# CM05: LEF escalado desde osu050 (OSU, AMI C5) por factor 25/3 -> lambda = 2.5 um, 2 metales.
# RESISTANCE/CAPACITANCE heredados de AMI C5: APROXIMADOS, no medidos en CM05.
# LEF file generated by Abstract Generator version 5.5.10 on Jul 31 16:51:52 2004
#
# Contains LEF for all bins.
# Options:   [x] Antenna
#            [x] Geometry
#            [x] Technology

VERSION 5.4 ;
NAMESCASESENSITIVE ON ;
BUSBITCHARS "[]" ;
DIVIDERCHAR "/" ;
UNITS
  DATABASE MICRONS 1000 ;
END UNITS

USEMINSPACING OBS ON ;
USEMINSPACING PIN OFF ;
CLEARANCEMEASURE EUCLIDEAN ;


MANUFACTURINGGRID 1.250 ;

LAYER nwell
  TYPE	MASTERSLICE ;
END nwell

LAYER nactive
  TYPE	MASTERSLICE ;
END nactive

LAYER pactive
  TYPE	MASTERSLICE ;
END pactive

LAYER poly
  TYPE	MASTERSLICE ;
END poly

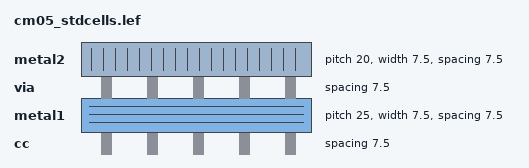
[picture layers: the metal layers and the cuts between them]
LAYER cc
  TYPE	CUT ;
  SPACING	7.500 ;
END cc

LAYER metal1
  TYPE		ROUTING ;
  DIRECTION	HORIZONTAL ;
  PITCH		25.000  ;
  OFFSET	12.500 ;
  WIDTH		7.500 ;
  SPACING	7.500 ;
  RESISTANCE	RPERSQ 0.09 ;
  CAPACITANCE	CPERSQDIST 3.2e-05 ;
END metal1

LAYER via
  TYPE	CUT ;
  SPACING	7.500 ;
END via

LAYER metal2
  TYPE		ROUTING ;
  DIRECTION	VERTICAL ;
  PITCH		20.000  ;
  OFFSET	10.000 ;
  WIDTH		7.500 ;
  SPACING	7.500 ;
  RESISTANCE	RPERSQ 0.09 ;
  CAPACITANCE	CPERSQDIST 1.6e-05 ;
END metal2




VIA M2_M1 DEFAULT
  LAYER metal1 ;
    RECT -5.000 -5.000 5.000 5.000 ;
  LAYER via ;
    RECT -2.500 -2.500 2.500 2.500 ;
  LAYER metal2 ;
    RECT -5.000 -5.000 5.000 5.000 ;
END M2_M1



VIARULE viagen21 GENERATE
  LAYER metal1 ;
    DIRECTION HORIZONTAL ;
    WIDTH 10.000 TO 1000.000 ;
    OVERHANG 2.500 ;
    METALOVERHANG 0.000 ;
  LAYER metal2 ;
    DIRECTION VERTICAL ;
    WIDTH 10.000 TO 1000.000 ;
    OVERHANG 2.500 ;
    METALOVERHANG 0.000 ;
  LAYER via ;
    RECT -2.500 -2.500 2.500 2.500 ;
    SPACING 12.500 BY 12.500 ;
END viagen21


VIARULE TURN1 GENERATE
  LAYER metal1 ;
    DIRECTION HORIZONTAL ;
  LAYER metal1 ;
    DIRECTION VERTICAL ;
END TURN1

VIARULE TURN2 GENERATE
  LAYER metal2 ;
    DIRECTION HORIZONTAL ;
  LAYER metal2 ;
    DIRECTION VERTICAL ;
END TURN2




SITE  core
    CLASS	CORE ;
    SYMMETRY	Y ;
    SIZE	20.000 BY 250.000 ;
END  core

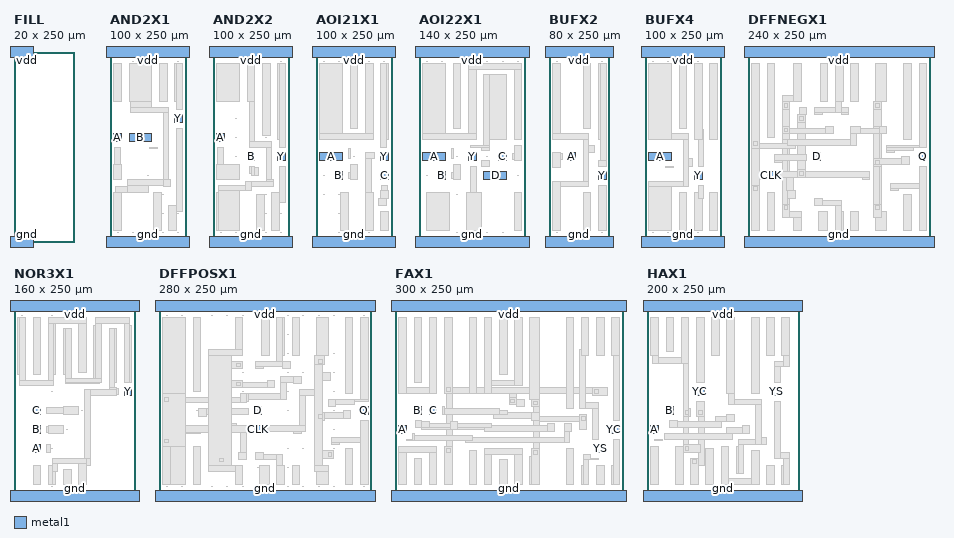
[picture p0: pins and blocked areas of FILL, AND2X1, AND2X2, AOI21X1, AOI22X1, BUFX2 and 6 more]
MACRO FILL
  CLASS  CORE ;
  FOREIGN FILL 0.000 0.000 ;
  ORIGIN 0.000 0.000 ;
  SIZE 20.000 BY 250.000 ;
  SYMMETRY X Y  ;
  SITE core ;
  PIN gnd
    DIRECTION INOUT ;
    USE GROUND ;
    SHAPE ABUTMENT ;
    PORT
      LAYER metal1 ;
        RECT -5.000 -7.500 25.000 7.500 ;
    END
  END gnd
  PIN vdd
    DIRECTION INOUT ;
    USE POWER ;
    SHAPE ABUTMENT ;
    PORT
      LAYER metal1 ;
        RECT -5.000 242.500 25.000 257.500 ;
    END
  END vdd
END FILL

MACRO AND2X1
  CLASS  CORE ;
  FOREIGN AND2X1 0.000 0.000 ;
  ORIGIN 0.000 0.000 ;
  SIZE 100.000 BY 250.000 ;
  SYMMETRY X Y  ;
  SITE core ;
  PIN A
    DIRECTION INPUT ;
    PORT
      LAYER metal1 ;
        RECT 5.000 132.500 15.000 142.500 ;
    END
  END A
  PIN B
    DIRECTION INPUT ;
    PORT
      LAYER metal1 ;
        RECT 25.000 132.500 55.000 142.500 ;
    END
  END B
  PIN gnd
    DIRECTION INOUT ;
    USE GROUND ;
    SHAPE ABUTMENT ;
    PORT
      LAYER metal1 ;
        RECT -5.000 -7.500 105.000 7.500 ;
    END
  END gnd
  PIN Y
    DIRECTION OUTPUT ;
    PORT
      LAYER metal1 ;
        RECT 85.000 157.500 95.000 167.500 ;
    END
  END Y
  PIN vdd
    DIRECTION INOUT ;
    USE POWER ;
    SHAPE ABUTMENT ;
    PORT
      LAYER metal1 ;
        RECT -5.000 242.500 105.000 257.500 ;
    END
  END vdd
  OBS
      LAYER metal1 ;
        RECT 9.375 11.875 10.625 13.125 ;
        RECT 29.375 11.875 30.625 13.125 ;
        RECT 29.375 236.875 30.625 238.125 ;
        RECT 49.375 11.875 50.625 13.125 ;
        RECT 49.375 86.875 50.625 88.125 ;
        RECT 49.375 236.875 50.625 238.125 ;
        RECT 69.375 11.875 70.625 13.125 ;
        RECT 69.375 36.875 70.625 38.125 ;
        RECT 69.375 61.875 70.625 63.125 ;
        RECT 89.375 11.875 90.625 13.125 ;
        RECT 89.375 36.875 90.625 38.125 ;
        RECT 89.375 236.875 90.625 238.125 ;
      LAYER metal1 ;
        RECT 57.500 15.000 67.500 65.000 ;
        RECT 6.250 102.500 13.750 125.000 ;
        RECT 5.000 82.500 15.000 102.500 ;
        RECT 52.500 122.500 62.500 125.000 ;
        RECT 87.500 40.000 95.000 150.000 ;
        RECT 77.500 15.000 87.500 47.500 ;
        RECT 5.000 185.000 15.000 235.000 ;
        RECT 22.500 65.000 50.000 75.000 ;
        RECT 5.000 15.000 15.000 65.000 ;
        RECT 7.500 65.000 22.500 72.500 ;
        RECT 22.500 75.000 70.000 82.500 ;
        RECT 27.500 170.000 77.500 177.500 ;
        RECT 70.000 72.500 80.000 82.500 ;
        RECT 70.000 82.500 77.500 170.000 ;
        RECT 25.000 185.000 55.000 235.000 ;
        RECT 27.500 177.500 55.000 185.000 ;
        RECT 65.000 185.000 75.000 235.000 ;
        RECT 85.000 185.000 87.500 235.000 ;
        RECT 87.500 175.000 95.000 235.000 ;
  END 
END AND2X1

MACRO AND2X2
  CLASS  CORE ;
  FOREIGN AND2X2 0.000 0.000 ;
  ORIGIN 0.000 0.000 ;
  SIZE 100.000 BY 250.000 ;
  SYMMETRY X Y  ;
  SITE core ;
  PIN A
    DIRECTION INPUT ;
    PORT
      LAYER metal1 ;
        RECT 5.000 132.500 15.000 142.500 ;
    END
  END A
  PIN B
    DIRECTION INPUT ;
    PORT
      LAYER metal1 ;
        RECT 45.000 107.500 55.000 117.500 ;
    END
  END B
  PIN gnd
    DIRECTION INOUT ;
    USE GROUND ;
    SHAPE ABUTMENT ;
    PORT
      LAYER metal1 ;
        RECT -5.000 -7.500 105.000 7.500 ;
    END
  END gnd
  PIN Y
    DIRECTION OUTPUT ;
    PORT
      LAYER metal1 ;
        RECT 85.000 107.500 95.000 117.500 ;
    END
  END Y
  PIN vdd
    DIRECTION INOUT ;
    USE POWER ;
    SHAPE ABUTMENT ;
    PORT
      LAYER metal1 ;
        RECT -5.000 242.500 105.000 257.500 ;
    END
  END vdd
  OBS
      LAYER metal1 ;
        RECT 9.375 11.875 10.625 13.125 ;
        RECT 29.375 11.875 30.625 13.125 ;
        RECT 29.375 111.875 30.625 113.125 ;
        RECT 29.375 136.875 30.625 138.125 ;
        RECT 29.375 161.875 30.625 163.125 ;
        RECT 49.375 11.875 50.625 13.125 ;
        RECT 49.375 236.875 50.625 238.125 ;
        RECT 69.375 11.875 70.625 13.125 ;
        RECT 69.375 36.875 70.625 38.125 ;
        RECT 69.375 61.875 70.625 63.125 ;
        RECT 69.375 136.875 70.625 138.125 ;
        RECT 89.375 11.875 90.625 13.125 ;
        RECT 89.375 36.875 90.625 38.125 ;
        RECT 89.375 236.875 90.625 238.125 ;
      LAYER metal1 ;
        RECT 57.500 15.000 67.500 62.500 ;
        RECT 55.000 87.500 60.000 97.500 ;
        RECT 47.500 90.000 50.000 100.000 ;
        RECT 50.000 87.500 55.000 100.000 ;
        RECT 87.500 52.500 95.000 100.000 ;
        RECT 77.500 15.000 87.500 65.000 ;
        RECT 6.250 102.500 13.750 125.000 ;
        RECT 5.000 82.500 35.000 102.500 ;
        RECT 5.000 185.000 35.000 235.000 ;
        RECT 47.500 125.000 77.500 132.500 ;
        RECT 70.000 80.000 80.000 82.500 ;
        RECT 70.000 82.500 77.500 125.000 ;
        RECT 42.500 67.500 50.000 80.000 ;
        RECT 50.000 72.500 80.000 80.000 ;
        RECT 45.000 185.000 55.000 235.000 ;
        RECT 47.500 132.500 55.000 185.000 ;
        RECT 7.500 15.000 35.000 67.500 ;
        RECT 5.000 15.000 7.500 65.000 ;
        RECT 7.500 67.500 42.500 75.000 ;
        RECT 65.000 140.000 75.000 235.000 ;
        RECT 85.000 135.000 87.500 235.000 ;
        RECT 87.500 125.000 95.000 235.000 ;
  END 
END AND2X2

MACRO AOI21X1
  CLASS  CORE ;
  FOREIGN AOI21X1 0.000 0.000 ;
  ORIGIN 0.000 0.000 ;
  SIZE 100.000 BY 250.000 ;
  SYMMETRY X Y  ;
  SITE core ;
  PIN A
    DIRECTION INPUT ;
    PORT
      LAYER metal1 ;
        RECT 5.000 107.500 35.000 117.500 ;
    END
  END A
  PIN B
    DIRECTION INPUT ;
    PORT
      LAYER metal1 ;
        RECT 25.000 82.500 35.000 92.500 ;
    END
  END B
  PIN C
    DIRECTION INPUT ;
    PORT
      LAYER metal1 ;
        RECT 85.000 82.500 95.000 92.500 ;
    END
  END C
  PIN gnd
    DIRECTION INOUT ;
    USE GROUND ;
    SHAPE ABUTMENT ;
    PORT
      LAYER metal1 ;
        RECT -5.000 -7.500 105.000 7.500 ;
    END
  END gnd
  PIN Y
    DIRECTION OUTPUT ;
    PORT
      LAYER metal1 ;
        RECT 85.000 107.500 95.000 117.500 ;
    END
  END Y
  PIN vdd
    DIRECTION INOUT ;
    USE POWER ;
    SHAPE ABUTMENT ;
    PORT
      LAYER metal1 ;
        RECT -5.000 242.500 105.000 257.500 ;
    END
  END vdd
  OBS
      LAYER metal1 ;
        RECT 9.375 61.875 10.625 63.125 ;
        RECT 9.375 86.875 10.625 88.125 ;
        RECT 9.375 236.875 10.625 238.125 ;
        RECT 29.375 11.875 30.625 13.125 ;
        RECT 29.375 36.875 30.625 38.125 ;
        RECT 29.375 61.875 30.625 63.125 ;
        RECT 29.375 236.875 30.625 238.125 ;
        RECT 49.375 11.875 50.625 13.125 ;
        RECT 49.375 111.875 50.625 113.125 ;
        RECT 69.375 11.875 70.625 13.125 ;
        RECT 69.375 236.875 70.625 238.125 ;
        RECT 89.375 236.875 90.625 238.125 ;
      LAYER metal1 ;
        RECT 85.000 15.000 95.000 40.000 ;
        RECT 32.500 15.000 42.500 65.000 ;
        RECT 86.250 67.500 93.750 75.000 ;
        RECT 85.000 57.500 95.000 67.500 ;
        RECT 82.500 47.500 92.500 57.500 ;
        RECT 45.000 82.500 55.000 102.500 ;
        RECT 42.500 83.750 45.000 91.250 ;
        RECT 65.000 15.000 75.000 65.000 ;
        RECT 65.000 65.000 72.500 110.000 ;
        RECT 65.000 110.000 77.500 117.500 ;
        RECT 42.500 110.000 45.000 122.500 ;
        RECT 45.000 150.000 55.000 235.000 ;
        RECT 5.000 142.500 35.000 235.000 ;
        RECT 65.000 142.500 75.000 235.000 ;
        RECT 5.000 135.000 75.000 142.500 ;
        RECT 85.000 125.000 92.500 235.000 ;
        RECT 92.500 135.000 95.000 235.000 ;
  END 
END AOI21X1

MACRO AOI22X1
  CLASS  CORE ;
  FOREIGN AOI22X1 0.000 0.000 ;
  ORIGIN 0.000 0.000 ;
  SIZE 140.000 BY 250.000 ;
  SYMMETRY X Y  ;
  SITE core ;
  PIN A
    DIRECTION INPUT ;
    PORT
      LAYER metal1 ;
        RECT 5.000 107.500 35.000 117.500 ;
    END
  END A
  PIN B
    DIRECTION INPUT ;
    PORT
      LAYER metal1 ;
        RECT 25.000 82.500 35.000 92.500 ;
    END
  END B
  PIN C
    DIRECTION INPUT ;
    PORT
      LAYER metal1 ;
        RECT 105.000 107.500 115.000 117.500 ;
    END
  END C
  PIN D
    DIRECTION INPUT ;
    PORT
      LAYER metal1 ;
        RECT 85.000 82.500 115.000 92.500 ;
    END
  END D
  PIN gnd
    DIRECTION INOUT ;
    USE GROUND ;
    SHAPE ABUTMENT ;
    PORT
      LAYER metal1 ;
        RECT -5.000 -7.500 145.000 7.500 ;
    END
  END gnd
  PIN Y
    DIRECTION OUTPUT ;
    PORT
      LAYER metal1 ;
        RECT 65.000 107.500 75.000 117.500 ;
    END
  END Y
  PIN vdd
    DIRECTION INOUT ;
    USE POWER ;
    SHAPE ABUTMENT ;
    PORT
      LAYER metal1 ;
        RECT -5.000 242.500 145.000 257.500 ;
    END
  END vdd
  OBS
      LAYER metal1 ;
        RECT 9.375 86.875 10.625 88.125 ;
        RECT 9.375 236.875 10.625 238.125 ;
        RECT 29.375 236.875 30.625 238.125 ;
        RECT 49.375 11.875 50.625 13.125 ;
        RECT 49.375 61.875 50.625 63.125 ;
        RECT 49.375 111.875 50.625 113.125 ;
        RECT 69.375 11.875 70.625 13.125 ;
        RECT 69.375 236.875 70.625 238.125 ;
        RECT 89.375 11.875 90.625 13.125 ;
        RECT 89.375 111.875 90.625 113.125 ;
        RECT 89.375 236.875 90.625 238.125 ;
        RECT 109.375 11.875 110.625 13.125 ;
        RECT 109.375 236.875 110.625 238.125 ;
        RECT 129.375 86.875 130.625 88.125 ;
        RECT 129.375 236.875 130.625 238.125 ;
      LAYER metal1 ;
        RECT 10.000 15.000 40.000 65.000 ;
        RECT 125.000 15.000 135.000 65.000 ;
        RECT 62.500 15.000 82.500 65.000 ;
        RECT 67.500 65.000 75.000 100.000 ;
        RECT 45.000 82.500 55.000 102.500 ;
        RECT 42.500 83.750 45.000 91.250 ;
        RECT 82.500 100.000 92.500 107.500 ;
        RECT 42.500 110.000 45.000 122.500 ;
        RECT 125.000 107.500 135.000 127.500 ;
        RECT 122.500 108.750 125.000 116.250 ;
        RECT 85.000 127.500 92.500 220.000 ;
        RECT 67.500 125.000 92.500 127.500 ;
        RECT 82.500 120.000 92.500 125.000 ;
        RECT 92.500 135.000 115.000 220.000 ;
        RECT 45.000 150.000 55.000 235.000 ;
        RECT 65.000 142.500 75.000 227.500 ;
        RECT 5.000 135.000 75.000 142.500 ;
        RECT 5.000 142.500 35.000 235.000 ;
        RECT 65.000 227.500 135.000 235.000 ;
        RECT 125.000 135.000 135.000 227.500 ;
  END 
END AOI22X1

MACRO BUFX2
  CLASS  CORE ;
  FOREIGN BUFX2 0.000 0.000 ;
  ORIGIN 0.000 0.000 ;
  SIZE 80.000 BY 250.000 ;
  SYMMETRY X Y  ;
  SITE core ;
  PIN A
    DIRECTION INPUT ;
    PORT
      LAYER metal1 ;
        RECT 25.000 107.500 35.000 117.500 ;
    END
  END A
  PIN gnd
    DIRECTION INOUT ;
    USE GROUND ;
    SHAPE ABUTMENT ;
    PORT
      LAYER metal1 ;
        RECT -5.000 -7.500 85.000 7.500 ;
    END
  END gnd
  PIN Y
    DIRECTION OUTPUT ;
    PORT
      LAYER metal1 ;
        RECT 65.000 82.500 75.000 92.500 ;
    END
  END Y
  PIN vdd
    DIRECTION INOUT ;
    USE POWER ;
    SHAPE ABUTMENT ;
    PORT
      LAYER metal1 ;
        RECT -5.000 242.500 85.000 257.500 ;
    END
  END vdd
  OBS
      LAYER metal1 ;
        RECT 9.375 11.875 10.625 13.125 ;
        RECT 9.375 236.875 10.625 238.125 ;
        RECT 29.375 11.875 30.625 13.125 ;
        RECT 29.375 236.875 30.625 238.125 ;
        RECT 69.375 11.875 70.625 13.125 ;
        RECT 69.375 236.875 70.625 238.125 ;
      LAYER metal1 ;
        RECT 45.000 15.000 55.000 65.000 ;
        RECT 65.000 15.000 75.000 75.000 ;
        RECT 5.000 97.500 15.000 117.500 ;
        RECT 15.000 108.750 17.500 116.250 ;
        RECT 52.500 117.500 60.000 127.500 ;
        RECT 5.000 135.000 52.500 142.500 ;
        RECT 5.000 142.500 15.000 235.000 ;
        RECT 5.000 15.000 15.000 80.000 ;
        RECT 45.000 80.000 52.500 135.000 ;
        RECT 15.000 72.500 52.500 80.000 ;
        RECT 45.000 150.000 55.000 235.000 ;
        RECT 65.000 135.000 67.500 235.000 ;
        RECT 67.500 107.500 75.000 235.000 ;
        RECT 65.000 100.000 75.000 107.500 ;
  END 
END BUFX2

MACRO BUFX4
  CLASS  CORE ;
  FOREIGN BUFX4 0.000 0.000 ;
  ORIGIN 0.000 0.000 ;
  SIZE 100.000 BY 250.000 ;
  SYMMETRY X Y  ;
  SITE core ;
  PIN A
    DIRECTION INPUT ;
    PORT
      LAYER metal1 ;
        RECT 5.000 107.500 35.000 117.500 ;
    END
  END A
  PIN gnd
    DIRECTION INOUT ;
    USE GROUND ;
    SHAPE ABUTMENT ;
    PORT
      LAYER metal1 ;
        RECT -5.000 -7.500 105.000 7.500 ;
    END
  END gnd
  PIN Y
    DIRECTION OUTPUT ;
    PORT
      LAYER metal1 ;
        RECT 65.000 82.500 75.000 92.500 ;
    END
  END Y
  PIN vdd
    DIRECTION INOUT ;
    USE POWER ;
    SHAPE ABUTMENT ;
    PORT
      LAYER metal1 ;
        RECT -5.000 242.500 105.000 257.500 ;
    END
  END vdd
  OBS 
      LAYER metal1 ;
        RECT 9.375 11.875 10.625 13.125 ;
        RECT 9.375 236.875 10.625 238.125 ;
        RECT 29.375 11.875 30.625 13.125 ;
        RECT 29.375 236.875 30.625 238.125 ;
        RECT 69.375 11.875 70.625 13.125 ;
        RECT 69.375 236.875 70.625 238.125 ;
      LAYER metal1 ;
        RECT 27.500 97.500 37.500 100.000 ;
        RECT 45.000 150.000 55.000 235.000 ;
        RECT 45.000 15.000 55.000 65.000 ;
        RECT 5.000 15.000 35.000 80.000 ;
        RECT 5.000 72.500 57.500 80.000 ;
        RECT 50.000 100.000 62.500 110.000 ;
        RECT 50.000 72.500 57.500 142.500 ;
        RECT 5.000 135.000 57.500 142.500 ;
        RECT 5.000 135.000 35.000 235.000 ;
        RECT 70.000 100.000 77.500 147.500 ;
        RECT 65.000 135.000 75.000 235.000 ;
        RECT 65.000 15.000 75.000 65.000 ;
        RECT 70.000 57.500 77.500 75.000 ;
        RECT 85.000 135.000 95.000 235.000 ;
        RECT 85.000 15.000 95.000 65.000 ;
  END 
END BUFX4

MACRO DFFNEGX1
  CLASS  CORE ;
  FOREIGN DFFNEGX1 0.000 0.000 ;
  ORIGIN 0.000 0.000 ;
  SIZE 240.000 BY 250.000 ;
  SYMMETRY X Y  ;
  SITE core ;
  PIN Q
    DIRECTION OUTPUT ;
    PORT
      LAYER metal1 ;
        RECT 225.000 107.500 235.000 117.500 ;
    END
  END Q
  PIN CLK
    DIRECTION INPUT ;
    PORT
      LAYER metal1 ;
        RECT 25.000 82.500 35.000 92.500 ;
    END
  END CLK
  PIN D
    DIRECTION INPUT ;
    PORT
      LAYER metal1 ;
        RECT 85.000 107.500 95.000 117.500 ;
    END
  END D
  PIN gnd
    DIRECTION INOUT ;
    USE GROUND ;
    SHAPE ABUTMENT ;
    PORT
      LAYER metal1 ;
        RECT -5.000 -7.500 245.000 7.500 ;
    END
  END gnd
  PIN vdd
    DIRECTION INOUT ;
    USE POWER ;
    SHAPE ABUTMENT ;
    PORT
      LAYER metal1 ;
        RECT -5.000 242.500 245.000 257.500 ;
    END
  END vdd
  OBS 
      LAYER metal2 ;
        RECT 5.000 65.000 15.000 135.000 ;
        RECT 45.000 40.000 55.000 125.000 ;
        RECT 45.000 40.000 52.500 185.000 ;
        RECT 45.000 135.000 55.000 185.000 ;
        RECT 65.000 85.000 75.000 167.500 ;
        RECT 165.000 40.000 175.000 142.500 ;
        RECT 165.000 40.000 172.500 185.000 ;
        RECT 165.000 152.500 175.000 185.000 ;
      LAYER metal1 ;
        RECT 5.000 15.000 15.000 75.000 ;
        RECT 15.000 82.500 17.500 92.500 ;
        RECT 25.000 137.500 35.000 235.000 ;
        RECT 25.000 15.000 35.000 65.000 ;
        RECT 45.000 175.000 55.000 192.500 ;
        RECT 45.000 185.000 70.000 192.500 ;
        RECT 60.000 185.000 70.000 235.000 ;
        RECT 60.000 15.000 70.000 40.000 ;
        RECT 45.000 32.500 70.000 40.000 ;
        RECT 45.000 32.500 55.000 50.000 ;
        RECT 65.000 157.500 75.000 167.500 ;
        RECT 67.500 167.500 77.500 177.500 ;
        RECT 35.000 105.000 45.000 115.000 ;
        RECT 35.000 107.500 77.500 115.000 ;
        RECT 95.000 185.000 105.000 235.000 ;
        RECT 92.500 15.000 105.000 40.000 ;
        RECT 45.000 142.500 112.500 150.000 ;
        RECT 45.000 142.500 55.000 152.500 ;
        RECT 102.500 142.500 112.500 152.500 ;
        RECT 115.000 15.000 125.000 40.000 ;
        RECT 115.000 15.000 122.500 55.000 ;
        RECT 87.500 47.500 122.500 55.000 ;
        RECT 87.500 47.500 97.500 57.500 ;
        RECT 87.500 167.500 97.500 177.500 ;
        RECT 122.500 167.500 132.500 177.500 ;
        RECT 87.500 170.000 132.500 177.500 ;
        RECT 115.000 170.000 122.500 235.000 ;
        RECT 115.000 185.000 125.000 235.000 ;
        RECT 135.000 185.000 145.000 235.000 ;
        RECT 135.000 15.000 145.000 40.000 ;
        RECT 52.500 57.500 62.500 67.500 ;
        RECT 50.000 67.500 60.000 92.500 ;
        RECT 150.000 82.500 160.000 92.500 ;
        RECT 42.500 85.000 160.000 92.500 ;
        RECT 65.000 85.000 75.000 95.000 ;
        RECT 165.000 175.000 175.000 185.000 ;
        RECT 167.500 185.000 182.500 235.000 ;
        RECT 5.000 122.500 62.500 130.000 ;
        RECT 52.500 127.500 142.500 135.000 ;
        RECT 135.000 127.500 142.500 152.500 ;
        RECT 135.000 142.500 182.500 150.000 ;
        RECT 135.000 142.500 147.500 152.500 ;
        RECT 172.500 142.500 182.500 152.500 ;
        RECT 5.000 122.500 15.000 235.000 ;
        RECT 167.500 15.000 182.500 40.000 ;
        RECT 165.000 32.500 175.000 50.000 ;
        RECT 165.000 100.000 175.000 110.000 ;
        RECT 165.000 102.500 212.500 110.000 ;
        RECT 202.500 102.500 212.500 112.500 ;
        RECT 205.000 135.000 215.000 235.000 ;
        RECT 205.000 15.000 215.000 62.500 ;
        RECT 182.500 117.500 192.500 127.500 ;
        RECT 182.500 120.000 217.500 127.500 ;
        RECT 182.500 125.000 235.000 127.500 ;
        RECT 225.000 125.000 235.000 235.000 ;
        RECT 187.500 67.500 197.500 77.500 ;
        RECT 187.500 70.000 235.000 77.500 ;
        RECT 225.000 15.000 235.000 100.000 ;
      LAYER via ;
        RECT 7.500 127.500 12.500 132.500 ;
        RECT 7.500 67.500 12.500 72.500 ;
        RECT 47.500 177.500 52.500 182.500 ;
        RECT 47.500 145.000 52.500 150.000 ;
        RECT 47.500 42.500 52.500 47.500 ;
        RECT 67.500 160.000 72.500 165.000 ;
        RECT 67.500 87.500 72.500 92.500 ;
        RECT 167.500 177.500 172.500 182.500 ;
        RECT 167.500 102.500 172.500 107.500 ;
        RECT 167.500 42.500 172.500 47.500 ;
  END 
END DFFNEGX1

MACRO NOR3X1
  CLASS  CORE ;
  FOREIGN NOR3X1 0.000 0.000 ;
  ORIGIN 0.000 0.000 ;
  SIZE 160.000 BY 250.000 ;
  SYMMETRY X Y  ;
  SITE core ;
  PIN A
    DIRECTION INPUT ;
    PORT
      LAYER metal1 ;
        RECT 25.000 57.500 35.000 67.500 ;
    END
  END A
  PIN B
    DIRECTION INPUT ;
    PORT
      LAYER metal1 ;
        RECT 25.000 82.500 35.000 92.500 ;
    END
  END B
  PIN C
    DIRECTION INPUT ;
    PORT
      LAYER metal1 ;
        RECT 25.000 107.500 35.000 117.500 ;
    END
  END C
  PIN gnd
    DIRECTION INOUT ;
    USE GROUND ;
    SHAPE ABUTMENT ;
    PORT
      LAYER metal1 ;
        RECT -5.000 -7.500 165.000 7.500 ;
    END
  END gnd
  PIN Y
    DIRECTION OUTPUT ;
    PORT
      LAYER metal1 ;
        RECT 145.000 132.500 155.000 142.500 ;
    END
  END Y
  PIN vdd
    DIRECTION INOUT ;
    USE POWER ;
    SHAPE ABUTMENT ;
    PORT
      LAYER metal1 ;
        RECT -5.000 242.500 165.000 257.500 ;
    END
  END vdd
  OBS
      LAYER metal1 ;
        RECT 9.375 236.875 10.625 238.125 ;
        RECT 49.375 11.875 50.625 13.125 ;
        RECT 49.375 61.875 50.625 63.125 ;
        RECT 49.375 136.875 50.625 138.125 ;
        RECT 49.375 236.875 50.625 238.125 ;
        RECT 69.375 86.875 70.625 88.125 ;
        RECT 69.375 236.875 70.625 238.125 ;
        RECT 89.375 11.875 90.625 13.125 ;
        RECT 89.375 111.875 90.625 113.125 ;
        RECT 89.375 236.875 90.625 238.125 ;
      LAYER metal1 ;
        RECT 65.000 15.000 75.000 35.000 ;
        RECT 25.000 15.000 35.000 40.000 ;
        RECT 42.500 57.500 47.500 67.500 ;
        RECT 42.500 83.750 45.000 91.250 ;
        RECT 45.000 82.500 65.000 92.500 ;
        RECT 42.500 108.750 65.000 116.250 ;
        RECT 65.000 107.500 85.000 117.500 ;
        RECT 50.000 15.000 55.000 32.500 ;
        RECT 50.000 32.500 57.500 42.500 ;
        RECT 45.000 15.000 50.000 40.000 ;
        RECT 92.500 50.000 100.000 140.000 ;
        RECT 125.000 140.000 135.000 142.500 ;
        RECT 125.000 142.500 132.500 220.000 ;
        RECT 132.500 150.000 135.000 220.000 ;
        RECT 100.000 132.500 135.000 140.000 ;
        RECT 135.000 133.750 137.500 141.250 ;
        RECT 50.000 42.500 95.000 50.000 ;
        RECT 85.000 15.000 95.000 42.500 ;
        RECT 95.000 40.000 100.000 50.000 ;
        RECT 25.000 160.000 35.000 235.000 ;
        RECT 45.000 152.500 52.500 227.500 ;
        RECT 52.500 160.000 55.000 227.500 ;
        RECT 7.500 145.000 52.500 152.500 ;
        RECT 5.000 160.000 7.500 235.000 ;
        RECT 7.500 152.500 15.000 235.000 ;
        RECT 45.000 227.500 95.000 235.000 ;
        RECT 85.000 162.500 95.000 227.500 ;
        RECT 65.000 160.000 67.500 220.000 ;
        RECT 67.500 155.000 75.000 220.000 ;
        RECT 107.500 155.000 115.000 227.500 ;
        RECT 105.000 155.000 107.500 225.000 ;
        RECT 67.500 147.500 112.500 150.000 ;
        RECT 67.500 150.000 115.000 155.000 ;
        RECT 107.500 227.500 152.500 235.000 ;
        RECT 152.500 150.000 155.000 225.000 ;
        RECT 145.000 150.000 152.500 227.500 ;
  END 
END NOR3X1

MACRO DFFPOSX1
  CLASS  CORE ;
  FOREIGN DFFPOSX1 0.000 0.000 ;
  ORIGIN 0.000 0.000 ;
  SIZE 280.000 BY 250.000 ;
  SYMMETRY X Y  ;
  SITE core ;
  PIN Q
    DIRECTION OUTPUT ;
    PORT
      LAYER metal1 ;
        RECT 265.000 107.500 275.000 117.500 ;
    END
  END Q
  PIN CLK
    DIRECTION INPUT ;
    PORT
      LAYER metal1 ;
        RECT 125.000 82.500 135.000 92.500 ;
    END
  END CLK
  PIN D
    DIRECTION INPUT ;
    PORT
      LAYER metal1 ;
        RECT 125.000 107.500 135.000 117.500 ;
    END
  END D
  PIN gnd
    DIRECTION INOUT ;
    USE GROUND ;
    SHAPE ABUTMENT ;
    PORT
      LAYER metal1 ;
        RECT -5.000 -7.500 285.000 7.500 ;
    END
  END gnd
  PIN vdd
    DIRECTION INOUT ;
    USE POWER ;
    SHAPE ABUTMENT ;
    PORT
      LAYER metal1 ;
        RECT -5.000 242.500 285.000 257.500 ;
    END
  END vdd
  OBS
      LAYER metal1 ;
        RECT 9.375 11.875 10.625 13.125 ;
        RECT 9.375 236.875 10.625 238.125 ;
        RECT 29.375 11.875 30.625 13.125 ;
        RECT 29.375 86.875 30.625 88.125 ;
        RECT 29.375 236.875 30.625 238.125 ;
        RECT 49.375 111.875 50.625 113.125 ;
        RECT 69.375 11.875 70.625 13.125 ;
        RECT 69.375 236.875 70.625 238.125 ;
        RECT 89.375 11.875 90.625 13.125 ;
        RECT 89.375 61.875 90.625 63.125 ;
        RECT 89.375 136.875 90.625 138.125 ;
        RECT 89.375 161.875 90.625 163.125 ;
        RECT 89.375 236.875 90.625 238.125 ;
        RECT 109.375 11.875 110.625 13.125 ;
        RECT 109.375 136.875 110.625 138.125 ;
        RECT 109.375 161.875 110.625 163.125 ;
        RECT 109.375 236.875 110.625 238.125 ;
        RECT 129.375 11.875 130.625 13.125 ;
        RECT 129.375 36.875 130.625 38.125 ;
        RECT 129.375 236.875 130.625 238.125 ;
        RECT 149.375 11.875 150.625 13.125 ;
        RECT 149.375 236.875 150.625 238.125 ;
        RECT 169.375 11.875 170.625 13.125 ;
        RECT 169.375 36.875 170.625 38.125 ;
        RECT 169.375 61.875 170.625 63.125 ;
        RECT 169.375 111.875 170.625 113.125 ;
        RECT 169.375 136.875 170.625 138.125 ;
        RECT 169.375 161.875 170.625 163.125 ;
        RECT 169.375 186.875 170.625 188.125 ;
        RECT 169.375 211.875 170.625 213.125 ;
        RECT 169.375 236.875 170.625 238.125 ;
        RECT 189.375 11.875 190.625 13.125 ;
        RECT 189.375 61.875 190.625 63.125 ;
        RECT 189.375 161.875 190.625 163.125 ;
        RECT 189.375 236.875 190.625 238.125 ;
        RECT 209.375 11.875 210.625 13.125 ;
        RECT 209.375 61.875 210.625 63.125 ;
        RECT 209.375 86.875 210.625 88.125 ;
        RECT 209.375 111.875 210.625 113.125 ;
        RECT 209.375 236.875 210.625 238.125 ;
        RECT 229.375 11.875 230.625 13.125 ;
        RECT 229.375 61.875 230.625 63.125 ;
        RECT 229.375 86.875 230.625 88.125 ;
        RECT 229.375 111.875 230.625 113.125 ;
        RECT 229.375 136.875 230.625 138.125 ;
        RECT 229.375 161.875 230.625 163.125 ;
        RECT 229.375 186.875 230.625 188.125 ;
        RECT 229.375 236.875 230.625 238.125 ;
        RECT 269.375 11.875 270.625 13.125 ;
        RECT 269.375 236.875 270.625 238.125 ;
      LAYER metal1 ;
        RECT 132.500 15.000 145.000 40.000 ;
        RECT 175.000 15.000 185.000 40.000 ;
        RECT 65.000 32.500 100.000 40.000 ;
        RECT 65.000 40.000 95.000 50.000 ;
        RECT 100.000 15.000 110.000 40.000 ;
        RECT 77.500 50.000 87.500 52.500 ;
        RECT 155.000 15.000 165.000 40.000 ;
        RECT 137.500 47.500 155.000 55.000 ;
        RECT 127.500 47.500 137.500 57.500 ;
        RECT 155.000 40.000 162.500 55.000 ;
        RECT 205.000 32.500 222.500 40.000 ;
        RECT 205.000 40.000 215.000 50.000 ;
        RECT 207.500 15.000 222.500 32.500 ;
        RECT 205.000 50.000 230.000 60.000 ;
        RECT 245.000 15.000 255.000 62.500 ;
        RECT 45.000 15.000 55.000 65.000 ;
        RECT 15.000 15.000 35.000 75.000 ;
        RECT 5.000 15.000 15.000 77.500 ;
        RECT 35.000 82.500 55.000 83.750 ;
        RECT 92.500 92.500 102.500 95.000 ;
        RECT 35.000 83.750 117.500 92.500 ;
        RECT 107.500 57.500 115.000 83.750 ;
        RECT 105.000 47.500 115.000 57.500 ;
        RECT 227.500 67.500 237.500 70.000 ;
        RECT 227.500 70.000 265.000 77.500 ;
        RECT 265.000 15.000 275.000 100.000 ;
        RECT 242.500 102.500 252.500 112.500 ;
        RECT 205.000 100.000 217.500 110.000 ;
        RECT 217.500 102.500 242.500 110.000 ;
        RECT 52.500 105.000 62.500 115.000 ;
        RECT 62.500 107.500 117.500 115.000 ;
        RECT 65.000 150.000 110.000 152.500 ;
        RECT 142.500 142.500 152.500 152.500 ;
        RECT 65.000 142.500 142.500 150.000 ;
        RECT 207.500 132.500 215.000 152.500 ;
        RECT 207.500 152.500 225.000 162.500 ;
        RECT 185.000 92.500 192.500 132.500 ;
        RECT 185.000 132.500 207.500 140.000 ;
        RECT 142.500 85.000 192.500 92.500 ;
        RECT 177.500 82.500 187.500 85.000 ;
        RECT 160.000 127.500 167.500 150.000 ;
        RECT 107.500 122.500 115.000 135.000 ;
        RECT 115.000 125.000 117.500 135.000 ;
        RECT 117.500 127.500 160.000 135.000 ;
        RECT 5.000 122.500 107.500 130.000 ;
        RECT 160.000 150.000 177.500 157.500 ;
        RECT 177.500 147.500 187.500 157.500 ;
        RECT 5.000 130.000 35.000 235.000 ;
        RECT 45.000 137.500 55.000 235.000 ;
        RECT 65.000 167.500 110.000 177.500 ;
        RECT 65.000 177.500 95.000 185.000 ;
        RECT 100.000 192.500 110.000 235.000 ;
        RECT 65.000 185.000 110.000 192.500 ;
        RECT 135.000 185.000 145.000 235.000 ;
        RECT 127.500 167.500 137.500 170.000 ;
        RECT 155.000 177.500 162.500 235.000 ;
        RECT 162.500 185.000 165.000 235.000 ;
        RECT 127.500 170.000 162.500 177.500 ;
        RECT 162.500 167.500 172.500 177.500 ;
        RECT 175.000 185.000 185.000 235.000 ;
        RECT 205.000 175.000 217.500 185.000 ;
        RECT 207.500 172.500 217.500 175.000 ;
        RECT 207.500 185.000 222.500 235.000 ;
        RECT 245.000 135.000 255.000 235.000 ;
        RECT 222.500 117.500 232.500 127.500 ;
        RECT 232.500 120.000 257.500 127.500 ;
        RECT 265.000 127.500 275.000 235.000 ;
        RECT 257.500 125.000 275.000 127.500 ;
      LAYER metal2 ;
        RECT 5.000 65.000 35.000 135.000 ;
        RECT 95.000 167.500 110.000 177.500 ;
        RECT 95.000 142.500 110.000 152.500 ;
        RECT 65.000 40.000 95.000 185.000 ;
        RECT 215.000 100.000 217.500 110.000 ;
        RECT 215.000 50.000 230.000 60.000 ;
        RECT 205.000 40.000 215.000 172.500 ;
        RECT 205.000 172.500 217.500 185.000 ;
      LAYER via ;
        RECT 80.000 45.000 85.000 50.000 ;
        RECT 222.500 52.500 227.500 57.500 ;
        RECT 7.500 70.000 12.500 75.000 ;
        RECT 210.000 102.500 215.000 107.500 ;
        RECT 7.500 125.000 12.500 130.000 ;
        RECT 102.500 145.000 107.500 150.000 ;
        RECT 102.500 170.000 107.500 175.000 ;
        RECT 210.000 175.000 215.000 180.000 ;
  END
END DFFPOSX1

MACRO FAX1
  CLASS  CORE ;
  FOREIGN FAX1 0.000 0.000 ;
  ORIGIN 0.000 0.000 ;
  SIZE 300.000 BY 250.000 ;
  SYMMETRY X Y  ;
  SITE core ;
  PIN YC
    DIRECTION OUTPUT ;
    PORT
      LAYER metal1 ;
        RECT 285.000 82.500 295.000 92.500 ;
    END
  END YC
  PIN YS
    DIRECTION OUTPUT ;
    PORT
      LAYER metal1 ;
        RECT 265.000 57.500 275.000 67.500 ;
    END
  END YS
  PIN A
    DIRECTION INPUT ;
    PORT
      LAYER metal1 ;
        RECT 5.000 82.500 15.000 92.500 ;
    END
  END A
  PIN B
    DIRECTION INPUT ;
    PORT
      LAYER metal1 ;
        RECT 25.000 107.500 35.000 117.500 ;
    END
  END B
  PIN C
    DIRECTION INPUT ;
    PORT
      LAYER metal1 ;
        RECT 45.000 107.500 55.000 117.500 ;
    END
  END C
  PIN gnd
    DIRECTION INOUT ;
    USE GROUND ;
    SHAPE ABUTMENT ;
    PORT
      LAYER metal1 ;
        RECT -5.000 -7.500 305.000 7.500 ;
    END
  END gnd
  PIN vdd
    DIRECTION INOUT ;
    USE POWER ;
    SHAPE ABUTMENT ;
    PORT
      LAYER metal1 ;
        RECT -5.000 242.500 305.000 257.500 ;
    END
  END vdd
  OBS 
      LAYER metal2 ;
        RECT 180.000 52.500 190.000 62.500 ;
        RECT 182.500 97.500 252.500 105.000 ;
        RECT 242.500 97.500 252.500 107.500 ;
        RECT 182.500 52.500 190.000 127.500 ;
        RECT 180.000 117.500 190.000 127.500 ;
        RECT 65.000 55.000 75.000 65.000 ;
        RECT 150.000 120.000 160.000 142.500 ;
        RECT 260.000 132.500 270.000 142.500 ;
        RECT 65.000 135.000 270.000 142.500 ;
        RECT 67.500 55.000 75.000 145.000 ;
        RECT 65.000 135.000 75.000 145.000 ;
      LAYER metal1 ;
        RECT 25.000 150.000 35.000 235.000 ;
        RECT 25.000 15.000 35.000 50.000 ;
        RECT 5.000 135.000 55.000 142.500 ;
        RECT 5.000 135.000 15.000 235.000 ;
        RECT 45.000 135.000 55.000 235.000 ;
        RECT 5.000 15.000 15.000 65.000 ;
        RECT 45.000 15.000 55.000 65.000 ;
        RECT 5.000 57.500 55.000 65.000 ;
        RECT 65.000 135.000 75.000 235.000 ;
        RECT 65.000 15.000 75.000 65.000 ;
        RECT 97.500 135.000 107.500 235.000 ;
        RECT 97.500 15.000 107.500 60.000 ;
        RECT 137.500 160.000 147.500 235.000 ;
        RECT 137.500 15.000 147.500 47.500 ;
        RECT 117.500 145.000 167.500 152.500 ;
        RECT 117.500 135.000 127.500 235.000 ;
        RECT 157.500 145.000 167.500 235.000 ;
        RECT 117.500 15.000 127.500 62.500 ;
        RECT 157.500 15.000 167.500 62.500 ;
        RECT 117.500 55.000 167.500 62.500 ;
        RECT 160.000 117.500 170.000 127.500 ;
        RECT 150.000 120.000 160.000 130.000 ;
        RECT 180.000 117.500 190.000 235.000 ;
        RECT 177.500 127.500 190.000 235.000 ;
        RECT 130.000 102.500 190.000 110.000 ;
        RECT 180.000 100.000 190.000 110.000 ;
        RECT 62.500 107.500 147.500 112.500 ;
        RECT 62.500 107.500 137.500 115.000 ;
        RECT 62.500 107.500 65.000 117.500 ;
        RECT 177.500 15.000 190.000 52.500 ;
        RECT 180.000 15.000 190.000 62.500 ;
        RECT 35.000 87.500 210.000 92.500 ;
        RECT 117.500 85.000 210.000 92.500 ;
        RECT 27.500 90.000 127.500 95.000 ;
        RECT 200.000 85.000 210.000 95.000 ;
        RECT 27.500 90.000 45.000 97.500 ;
        RECT 72.500 87.500 82.500 97.500 ;
        RECT 27.500 90.000 35.000 100.000 ;
        RECT 15.000 72.500 230.000 75.000 ;
        RECT 92.500 70.000 230.000 77.500 ;
        RECT 22.500 72.500 102.500 80.000 ;
        RECT 22.500 72.500 25.000 82.500 ;
        RECT 222.500 70.000 230.000 95.000 ;
        RECT 222.500 85.000 232.500 95.000 ;
        RECT 225.000 115.000 235.000 235.000 ;
        RECT 225.000 15.000 235.000 62.500 ;
        RECT 242.500 87.500 252.500 107.500 ;
        RECT 260.000 75.000 267.500 122.500 ;
        RECT 242.500 115.000 267.500 122.500 ;
        RECT 242.500 115.000 250.000 192.500 ;
        RECT 245.000 185.000 255.000 235.000 ;
        RECT 245.000 15.000 255.000 40.000 ;
        RECT 247.500 15.000 255.000 55.000 ;
        RECT 247.500 47.500 267.500 50.000 ;
        RECT 247.500 47.500 257.500 55.000 ;
        RECT 265.000 185.000 275.000 235.000 ;
        RECT 265.000 15.000 275.000 40.000 ;
        RECT 260.000 132.500 280.000 142.500 ;
        RECT 287.500 100.000 295.000 235.000 ;
        RECT 285.000 185.000 295.000 235.000 ;
        RECT 285.000 15.000 295.000 40.000 ;
        RECT 287.500 15.000 295.000 75.000 ;
      LAYER via ;
        RECT 67.500 137.500 72.500 142.500 ;
        RECT 67.500 57.500 72.500 62.500 ;
        RECT 152.500 122.500 157.500 127.500 ;
        RECT 182.500 120.000 187.500 125.000 ;
        RECT 182.500 55.000 187.500 60.000 ;
        RECT 245.000 100.000 250.000 105.000 ;
        RECT 262.500 135.000 267.500 140.000 ;
  END 
END FAX1

MACRO HAX1
  CLASS  CORE ;
  FOREIGN HAX1 0.000 0.000 ;
  ORIGIN 0.000 0.000 ;
  SIZE 200.000 BY 250.000 ;
  SYMMETRY X Y  ;
  SITE core ;
  PIN YC
    DIRECTION OUTPUT ;
    PORT
      LAYER metal1 ;
        RECT 65.000 132.500 75.000 142.500 ;
    END
  END YC
  PIN YS
    DIRECTION OUTPUT ;
    PORT
      LAYER metal1 ;
        RECT 165.000 132.500 175.000 142.500 ;
    END
  END YS
  PIN A
    DIRECTION INPUT ;
    PORT
      LAYER metal1 ;
        RECT 5.000 82.500 15.000 92.500 ;
    END
  END A
  PIN B
    DIRECTION INPUT ;
    PORT
      LAYER metal1 ;
        RECT 25.000 107.500 35.000 117.500 ;
    END
  END B
  PIN gnd
    DIRECTION INOUT ;
    USE GROUND ;
    SHAPE ABUTMENT ;
    PORT
      LAYER metal1 ;
        RECT -5.000 -7.500 205.000 7.500 ;
    END
  END gnd
  PIN vdd
    DIRECTION INOUT ;
    USE POWER ;
    SHAPE ABUTMENT ;
    PORT
      LAYER metal1 ;
        RECT -5.000 242.500 205.000 257.500 ;
    END
  END vdd
  OBS 
      LAYER metal2 ;
        RECT 47.500 57.500 57.500 67.500 ;
        RECT 47.500 57.500 55.000 115.000 ;
        RECT 47.500 105.000 57.500 115.000 ;
        RECT 57.500 40.000 75.000 50.000 ;
        RECT 67.500 40.000 75.000 115.000 ;
        RECT 65.000 105.000 75.000 115.000 ;
      LAYER metal1 ;
        RECT 5.000 15.000 15.000 65.000 ;
        RECT 10.000 72.500 20.000 75.000 ;
        RECT 25.000 190.000 35.000 235.000 ;
        RECT 47.500 105.000 57.500 115.000 ;
        RECT 7.500 175.000 55.000 182.500 ;
        RECT 7.500 175.000 15.000 235.000 ;
        RECT 5.000 185.000 15.000 235.000 ;
        RECT 47.500 105.000 55.000 235.000 ;
        RECT 45.000 175.000 55.000 235.000 ;
        RECT 57.500 15.000 67.500 50.000 ;
        RECT 37.500 15.000 47.500 65.000 ;
        RECT 47.500 57.500 70.000 67.500 ;
        RECT 65.000 150.000 75.000 235.000 ;
        RECT 65.000 105.000 75.000 125.000 ;
        RECT 77.500 15.000 87.500 62.500 ;
        RECT 85.000 185.000 95.000 235.000 ;
        RECT 30.000 90.000 97.500 97.500 ;
        RECT 30.000 90.000 40.000 100.000 ;
        RECT 90.000 97.500 115.000 105.000 ;
        RECT 105.000 97.500 115.000 107.500 ;
        RECT 22.500 75.000 112.500 82.500 ;
        RECT 105.000 82.500 135.000 90.000 ;
        RECT 125.000 82.500 135.000 92.500 ;
        RECT 137.500 135.000 147.500 235.000 ;
        RECT 97.500 15.000 147.500 22.500 ;
        RECT 137.500 15.000 147.500 60.000 ;
        RECT 97.500 15.000 107.500 65.000 ;
        RECT 117.500 30.000 127.500 65.000 ;
        RECT 120.000 30.000 127.500 75.000 ;
        RECT 120.000 67.500 157.500 75.000 ;
        RECT 142.500 67.500 157.500 77.500 ;
        RECT 142.500 67.500 150.000 127.500 ;
        RECT 107.500 120.000 150.000 127.500 ;
        RECT 107.500 120.000 115.000 235.000 ;
        RECT 105.000 135.000 115.000 235.000 ;
        RECT 157.500 185.000 167.500 235.000 ;
        RECT 157.500 15.000 167.500 40.000 ;
        RECT 167.500 150.000 175.000 177.500 ;
        RECT 167.500 170.000 187.500 177.500 ;
        RECT 180.000 170.000 187.500 235.000 ;
        RECT 177.500 185.000 187.500 235.000 ;
        RECT 177.500 15.000 187.500 40.000 ;
        RECT 180.000 15.000 187.500 57.500 ;
        RECT 167.500 50.000 187.500 57.500 ;
        RECT 167.500 50.000 175.000 125.000 ;
      LAYER via ;
        RECT 50.000 107.500 55.000 112.500 ;
        RECT 50.000 60.000 55.000 65.000 ;
        RECT 60.000 42.500 65.000 47.500 ;
        RECT 67.500 107.500 72.500 112.500 ;
  END 
END HAX1

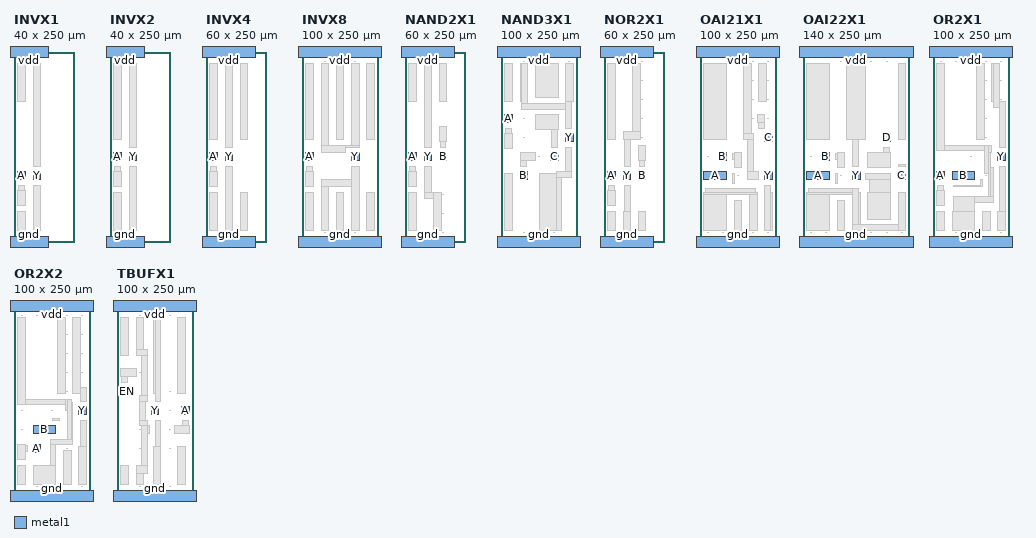
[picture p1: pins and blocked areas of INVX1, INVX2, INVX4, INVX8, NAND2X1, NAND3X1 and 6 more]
MACRO INVX1
  CLASS  CORE ;
  FOREIGN INVX1 0.000 0.000 ;
  ORIGIN 0.000 0.000 ;
  SIZE 40.000 BY 250.000 ;
  SYMMETRY X Y  ;
  SITE core ;
  PIN A
    DIRECTION INPUT ;
    PORT
      LAYER metal1 ;
        RECT 5.000 82.500 15.000 92.500 ;
    END
  END A
  PIN gnd
    DIRECTION INOUT ;
    USE GROUND ;
    SHAPE ABUTMENT ;
    PORT
      LAYER metal1 ;
        RECT -5.000 -7.500 45.000 7.500 ;
    END
  END gnd
  PIN Y
    DIRECTION OUTPUT ;
    PORT
      LAYER metal1 ;
        RECT 25.000 82.500 35.000 92.500 ;
    END
  END Y
  PIN vdd
    DIRECTION INOUT ;
    USE POWER ;
    SHAPE ABUTMENT ;
    PORT
      LAYER metal1 ;
        RECT -5.000 242.500 45.000 257.500 ;
    END
  END vdd
  OBS
      LAYER metal1 ;
        RECT 29.375 11.875 30.625 13.125 ;
        RECT 29.375 236.875 30.625 238.125 ;
      LAYER metal1 ;
        RECT 5.000 15.000 15.000 40.000 ;
        RECT 6.250 67.500 13.750 75.000 ;
        RECT 5.000 47.500 15.000 67.500 ;
        RECT 25.000 15.000 35.000 75.000 ;
        RECT 5.000 185.000 15.000 235.000 ;
        RECT 25.000 100.000 35.000 235.000 ;
  END 
END INVX1

MACRO INVX2
  CLASS  CORE ;
  FOREIGN INVX2 0.000 0.000 ;
  ORIGIN 0.000 0.000 ;
  SIZE 40.000 BY 250.000 ;
  SYMMETRY X Y  ;
  SITE core ;
  PIN A
    DIRECTION INPUT ;
    PORT
      LAYER metal1 ;
        RECT 5.000 107.500 15.000 117.500 ;
    END
  END A
  PIN gnd
    DIRECTION INOUT ;
    USE GROUND ;
    SHAPE ABUTMENT ;
    PORT
      LAYER metal1 ;
        RECT -5.000 -7.500 45.000 7.500 ;
    END
  END gnd
  PIN Y
    DIRECTION OUTPUT ;
    PORT
      LAYER metal1 ;
        RECT 25.000 107.500 35.000 117.500 ;
    END
  END Y
  PIN vdd
    DIRECTION INOUT ;
    USE POWER ;
    SHAPE ABUTMENT ;
    PORT
      LAYER metal1 ;
        RECT -5.000 242.500 45.000 257.500 ;
    END
  END vdd
  OBS
      LAYER metal1 ;
        RECT 29.375 11.875 30.625 13.125 ;
        RECT 29.375 236.875 30.625 238.125 ;
      LAYER metal1 ;
        RECT 5.000 15.000 15.000 65.000 ;
        RECT 6.250 92.500 13.750 100.000 ;
        RECT 5.000 72.500 15.000 92.500 ;
        RECT 25.000 15.000 35.000 100.000 ;
        RECT 5.000 135.000 15.000 235.000 ;
        RECT 25.000 125.000 35.000 235.000 ;
  END 
END INVX2

MACRO INVX4
  CLASS  CORE ;
  FOREIGN INVX4 0.000 0.000 ;
  ORIGIN 0.000 0.000 ;
  SIZE 60.000 BY 250.000 ;
  SYMMETRY X Y  ;
  SITE core ;
  PIN A
    DIRECTION INPUT ;
    PORT
      LAYER metal1 ;
        RECT 5.000 107.500 15.000 117.500 ;
    END
  END A
  PIN gnd
    DIRECTION INOUT ;
    USE GROUND ;
    SHAPE ABUTMENT ;
    PORT
      LAYER metal1 ;
        RECT -5.000 -7.500 65.000 7.500 ;
    END
  END gnd
  PIN Y
    DIRECTION OUTPUT ;
    PORT
      LAYER metal1 ;
        RECT 25.000 107.500 35.000 117.500 ;
    END
  END Y
  PIN vdd
    DIRECTION INOUT ;
    USE POWER ;
    SHAPE ABUTMENT ;
    PORT
      LAYER metal1 ;
        RECT -5.000 242.500 65.000 257.500 ;
    END
  END vdd
  OBS
      LAYER metal1 ;
        RECT 29.375 11.875 30.625 13.125 ;
        RECT 29.375 236.875 30.625 238.125 ;
      LAYER metal1 ;
        RECT 5.000 15.000 15.000 65.000 ;
        RECT 45.000 15.000 55.000 65.000 ;
        RECT 6.250 92.500 13.750 100.000 ;
        RECT 5.000 72.500 15.000 92.500 ;
        RECT 25.000 15.000 35.000 100.000 ;
        RECT 5.000 135.000 15.000 235.000 ;
        RECT 25.000 125.000 35.000 235.000 ;
        RECT 45.000 135.000 55.000 235.000 ;
  END 
END INVX4

MACRO INVX8
  CLASS  CORE ;
  FOREIGN INVX8 0.000 0.000 ;
  ORIGIN 0.000 0.000 ;
  SIZE 100.000 BY 250.000 ;
  SYMMETRY X Y  ;
  SITE core ;
  PIN A
    DIRECTION INPUT ;
    PORT
      LAYER metal1 ;
        RECT 5.000 107.500 15.000 117.500 ;
    END
  END A
  PIN gnd
    DIRECTION INOUT ;
    USE GROUND ;
    SHAPE ABUTMENT ;
    PORT
      LAYER metal1 ;
        RECT -5.000 -7.500 105.000 7.500 ;
    END
  END gnd
  PIN Y
    DIRECTION OUTPUT ;
    PORT
      LAYER metal1 ;
        RECT 65.000 107.500 75.000 117.500 ;
    END
  END Y
  PIN vdd
    DIRECTION INOUT ;
    USE POWER ;
    SHAPE ABUTMENT ;
    PORT
      LAYER metal1 ;
        RECT -5.000 242.500 105.000 257.500 ;
    END
  END vdd
  OBS
      LAYER metal1 ;
        RECT 29.375 11.875 30.625 13.125 ;
        RECT 29.375 236.875 30.625 238.125 ;
        RECT 69.375 11.875 70.625 13.125 ;
        RECT 69.375 236.875 70.625 238.125 ;
      LAYER metal1 ;
        RECT 5.000 15.000 15.000 65.000 ;
        RECT 45.000 15.000 55.000 65.000 ;
        RECT 85.000 15.000 95.000 65.000 ;
        RECT 6.250 92.500 13.750 100.000 ;
        RECT 5.000 72.500 15.000 92.500 ;
        RECT 25.000 15.000 35.000 72.500 ;
        RECT 25.000 72.500 65.000 82.500 ;
        RECT 65.000 15.000 75.000 100.000 ;
        RECT 5.000 135.000 15.000 235.000 ;
        RECT 45.000 135.000 55.000 235.000 ;
        RECT 25.000 127.500 35.000 235.000 ;
        RECT 25.000 117.500 57.500 127.500 ;
        RECT 65.000 127.500 75.000 235.000 ;
        RECT 57.500 125.000 75.000 127.500 ;
        RECT 85.000 135.000 95.000 235.000 ;
  END 
END INVX8

MACRO NAND2X1
  CLASS  CORE ;
  FOREIGN NAND2X1 0.000 0.000 ;
  ORIGIN 0.000 0.000 ;
  SIZE 60.000 BY 250.000 ;
  SYMMETRY X Y  ;
  SITE core ;
  PIN A
    DIRECTION INPUT ;
    PORT
      LAYER metal1 ;
        RECT 5.000 107.500 15.000 117.500 ;
    END
  END A
  PIN B
    DIRECTION INPUT ;
    PORT
      LAYER metal1 ;
        RECT 45.000 107.500 55.000 117.500 ;
    END
  END B
  PIN gnd
    DIRECTION INOUT ;
    USE GROUND ;
    SHAPE ABUTMENT ;
    PORT
      LAYER metal1 ;
        RECT -5.000 -7.500 65.000 7.500 ;
    END
  END gnd
  PIN Y
    DIRECTION OUTPUT ;
    PORT
      LAYER metal1 ;
        RECT 25.000 107.500 35.000 117.500 ;
    END
  END Y
  PIN vdd
    DIRECTION INOUT ;
    USE POWER ;
    SHAPE ABUTMENT ;
    PORT
      LAYER metal1 ;
        RECT -5.000 242.500 65.000 257.500 ;
    END
  END vdd
  OBS
      LAYER metal1 ;
        RECT 29.375 11.875 30.625 13.125 ;
        RECT 29.375 236.875 30.625 238.125 ;
        RECT 49.375 11.875 50.625 13.125 ;
        RECT 49.375 36.875 50.625 38.125 ;
        RECT 49.375 61.875 50.625 63.125 ;
      LAYER metal1 ;
        RECT 5.000 15.000 15.000 65.000 ;
        RECT 6.250 92.500 13.750 100.000 ;
        RECT 5.000 72.500 15.000 92.500 ;
        RECT 25.000 57.500 37.500 65.000 ;
        RECT 25.000 65.000 35.000 100.000 ;
        RECT 37.500 15.000 47.500 65.000 ;
        RECT 45.000 132.500 55.000 152.500 ;
        RECT 46.250 125.000 53.750 132.500 ;
        RECT 5.000 185.000 15.000 235.000 ;
        RECT 25.000 125.000 35.000 235.000 ;
        RECT 45.000 185.000 55.000 235.000 ;
  END 
END NAND2X1

MACRO NAND3X1
  CLASS  CORE ;
  FOREIGN NAND3X1 0.000 0.000 ;
  ORIGIN 0.000 0.000 ;
  SIZE 100.000 BY 250.000 ;
  SYMMETRY X Y  ;
  SITE core ;
  PIN A
    DIRECTION INPUT ;
    PORT
      LAYER metal1 ;
        RECT 5.000 157.500 15.000 167.500 ;
    END
  END A
  PIN B
    DIRECTION INPUT ;
    PORT
      LAYER metal1 ;
        RECT 25.000 82.500 35.000 92.500 ;
    END
  END B
  PIN C
    DIRECTION INPUT ;
    PORT
      LAYER metal1 ;
        RECT 65.000 107.500 75.000 117.500 ;
    END
  END C
  PIN gnd
    DIRECTION INOUT ;
    USE GROUND ;
    SHAPE ABUTMENT ;
    PORT
      LAYER metal1 ;
        RECT -5.000 -7.500 105.000 7.500 ;
    END
  END gnd
  PIN Y
    DIRECTION OUTPUT ;
    PORT
      LAYER metal1 ;
        RECT 85.000 132.500 95.000 142.500 ;
    END
  END Y
  PIN vdd
    DIRECTION INOUT ;
    USE POWER ;
    SHAPE ABUTMENT ;
    PORT
      LAYER metal1 ;
        RECT -5.000 242.500 105.000 257.500 ;
    END
  END vdd
  OBS
      LAYER metal1 ;
        RECT 29.375 11.875 30.625 13.125 ;
        RECT 29.375 136.875 30.625 138.125 ;
        RECT 29.375 161.875 30.625 163.125 ;
        RECT 29.375 236.875 30.625 238.125 ;
        RECT 49.375 11.875 50.625 13.125 ;
        RECT 49.375 111.875 50.625 113.125 ;
        RECT 69.375 11.875 70.625 13.125 ;
        RECT 89.375 236.875 90.625 238.125 ;
      LAYER metal1 ;
        RECT 5.000 15.000 15.000 90.000 ;
        RECT 25.000 107.500 45.000 117.500 ;
        RECT 26.250 100.000 33.750 107.500 ;
        RECT 85.000 92.500 92.500 125.000 ;
        RECT 72.500 15.000 80.000 85.000 ;
        RECT 72.500 85.000 92.500 92.500 ;
        RECT 50.000 15.000 72.500 90.000 ;
        RECT 6.250 142.500 13.750 150.000 ;
        RECT 5.000 122.500 15.000 142.500 ;
        RECT 45.000 147.500 75.000 167.500 ;
        RECT 66.250 125.000 73.750 147.500 ;
        RECT 5.000 185.000 15.000 235.000 ;
        RECT 45.000 190.000 75.000 235.000 ;
        RECT 25.000 185.000 27.500 235.000 ;
        RECT 27.500 182.500 35.000 235.000 ;
        RECT 27.500 175.000 85.000 182.500 ;
        RECT 85.000 150.000 92.500 185.000 ;
        RECT 85.000 185.000 95.000 235.000 ;
  END 
END NAND3X1

MACRO NOR2X1
  CLASS  CORE ;
  FOREIGN NOR2X1 0.000 0.000 ;
  ORIGIN 0.000 0.000 ;
  SIZE 60.000 BY 250.000 ;
  SYMMETRY X Y  ;
  SITE core ;
  PIN A
    DIRECTION INPUT ;
    PORT
      LAYER metal1 ;
        RECT 5.000 82.500 15.000 92.500 ;
    END
  END A
  PIN B
    DIRECTION INPUT ;
    PORT
      LAYER metal1 ;
        RECT 45.000 82.500 55.000 92.500 ;
    END
  END B
  PIN gnd
    DIRECTION INOUT ;
    USE GROUND ;
    SHAPE ABUTMENT ;
    PORT
      LAYER metal1 ;
        RECT -5.000 -7.500 65.000 7.500 ;
    END
  END gnd
  PIN Y
    DIRECTION OUTPUT ;
    PORT
      LAYER metal1 ;
        RECT 25.000 82.500 35.000 92.500 ;
    END
  END Y
  PIN vdd
    DIRECTION INOUT ;
    USE POWER ;
    SHAPE ABUTMENT ;
    PORT
      LAYER metal1 ;
        RECT -5.000 242.500 65.000 257.500 ;
    END
  END vdd
  OBS
      LAYER metal1 ;
        RECT 29.375 11.875 30.625 13.125 ;
        RECT 29.375 236.875 30.625 238.125 ;
        RECT 49.375 136.875 50.625 138.125 ;
        RECT 49.375 161.875 50.625 163.125 ;
        RECT 49.375 186.875 50.625 188.125 ;
        RECT 49.375 211.875 50.625 213.125 ;
        RECT 49.375 236.875 50.625 238.125 ;
      LAYER metal1 ;
        RECT 5.000 15.000 15.000 40.000 ;
        RECT 45.000 15.000 55.000 40.000 ;
        RECT 6.250 67.500 13.750 75.000 ;
        RECT 5.000 47.500 15.000 67.500 ;
        RECT 27.500 40.000 35.000 75.000 ;
        RECT 25.000 15.000 35.000 40.000 ;
        RECT 45.000 107.500 55.000 127.500 ;
        RECT 46.250 100.000 53.750 107.500 ;
        RECT 5.000 135.000 15.000 235.000 ;
        RECT 37.500 145.000 47.500 235.000 ;
        RECT 27.500 100.000 35.000 135.000 ;
        RECT 25.000 135.000 47.500 145.000 ;
  END 
END NOR2X1

MACRO OAI21X1
  CLASS  CORE ;
  FOREIGN OAI21X1 0.000 0.000 ;
  ORIGIN 0.000 0.000 ;
  SIZE 100.000 BY 250.000 ;
  SYMMETRY X Y  ;
  SITE core ;
  PIN A
    DIRECTION INPUT ;
    PORT
      LAYER metal1 ;
        RECT 5.000 82.500 35.000 92.500 ;
    END
  END A
  PIN B
    DIRECTION INPUT ;
    PORT
      LAYER metal1 ;
        RECT 25.000 107.500 35.000 117.500 ;
    END
  END B
  PIN C
    DIRECTION INPUT ;
    PORT
      LAYER metal1 ;
        RECT 85.000 132.500 95.000 142.500 ;
    END
  END C
  PIN gnd
    DIRECTION INOUT ;
    USE GROUND ;
    SHAPE ABUTMENT ;
    PORT
      LAYER metal1 ;
        RECT -5.000 -7.500 105.000 7.500 ;
    END
  END gnd
  PIN Y
    DIRECTION OUTPUT ;
    PORT
      LAYER metal1 ;
        RECT 85.000 82.500 95.000 92.500 ;
    END
  END Y
  PIN vdd
    DIRECTION INOUT ;
    USE POWER ;
    SHAPE ABUTMENT ;
    PORT
      LAYER metal1 ;
        RECT -5.000 242.500 105.000 257.500 ;
    END
  END vdd
  OBS
      LAYER metal1 ;
        RECT 9.375 11.875 10.625 13.125 ;
        RECT 9.375 111.875 10.625 113.125 ;
        RECT 29.375 11.875 30.625 13.125 ;
        RECT 49.375 86.875 50.625 88.125 ;
        RECT 49.375 236.875 50.625 238.125 ;
        RECT 69.375 11.875 70.625 13.125 ;
        RECT 69.375 161.875 70.625 163.125 ;
        RECT 69.375 186.875 70.625 188.125 ;
        RECT 69.375 211.875 70.625 213.125 ;
        RECT 69.375 236.875 70.625 238.125 ;
        RECT 89.375 11.875 90.625 13.125 ;
        RECT 89.375 161.875 90.625 163.125 ;
        RECT 89.375 186.875 90.625 188.125 ;
        RECT 89.375 211.875 90.625 213.125 ;
        RECT 89.375 236.875 90.625 238.125 ;
      LAYER metal1 ;
        RECT 45.000 15.000 55.000 55.000 ;
        RECT 5.000 15.000 35.000 62.500 ;
        RECT 7.500 65.000 72.500 70.000 ;
        RECT 5.000 62.500 75.000 65.000 ;
        RECT 65.000 15.000 75.000 62.500 ;
        RECT 92.500 15.000 95.000 65.000 ;
        RECT 85.000 15.000 92.500 75.000 ;
        RECT 42.500 77.500 45.000 90.000 ;
        RECT 42.500 108.750 45.000 116.250 ;
        RECT 45.000 97.500 55.000 117.500 ;
        RECT 75.000 157.500 85.000 167.500 ;
        RECT 77.500 150.000 85.000 157.500 ;
        RECT 5.000 135.000 35.000 235.000 ;
        RECT 62.500 82.500 77.500 92.500 ;
        RECT 57.500 135.000 70.000 142.500 ;
        RECT 62.500 92.500 70.000 135.000 ;
        RECT 57.500 142.500 67.500 235.000 ;
        RECT 77.500 185.000 87.500 235.000 ;
  END 
END OAI21X1

MACRO OAI22X1
  CLASS  CORE ;
  FOREIGN OAI22X1 0.000 0.000 ;
  ORIGIN 0.000 0.000 ;
  SIZE 140.000 BY 250.000 ;
  SYMMETRY X Y  ;
  SITE core ;
  PIN A
    DIRECTION INPUT ;
    PORT
      LAYER metal1 ;
        RECT 5.000 82.500 35.000 92.500 ;
    END
  END A
  PIN B
    DIRECTION INPUT ;
    PORT
      LAYER metal1 ;
        RECT 25.000 107.500 35.000 117.500 ;
    END
  END B
  PIN C
    DIRECTION INPUT ;
    PORT
      LAYER metal1 ;
        RECT 125.000 82.500 135.000 92.500 ;
    END
  END C
  PIN D
    DIRECTION INPUT ;
    PORT
      LAYER metal1 ;
        RECT 105.000 132.500 115.000 142.500 ;
    END
  END D
  PIN gnd
    DIRECTION INOUT ;
    USE GROUND ;
    SHAPE ABUTMENT ;
    PORT
      LAYER metal1 ;
        RECT -5.000 -7.500 145.000 7.500 ;
    END
  END gnd
  PIN Y
    DIRECTION OUTPUT ;
    PORT
      LAYER metal1 ;
        RECT 65.000 82.500 75.000 92.500 ;
    END
  END Y
  PIN vdd
    DIRECTION INOUT ;
    USE POWER ;
    SHAPE ABUTMENT ;
    PORT
      LAYER metal1 ;
        RECT -5.000 242.500 145.000 257.500 ;
    END
  END vdd
  OBS
      LAYER metal1 ;
        RECT 9.375 11.875 10.625 13.125 ;
        RECT 9.375 111.875 10.625 113.125 ;
        RECT 29.375 11.875 30.625 13.125 ;
        RECT 49.375 86.875 50.625 88.125 ;
        RECT 49.375 236.875 50.625 238.125 ;
        RECT 69.375 11.875 70.625 13.125 ;
        RECT 69.375 236.875 70.625 238.125 ;
        RECT 89.375 11.875 90.625 13.125 ;
        RECT 89.375 236.875 90.625 238.125 ;
        RECT 109.375 11.875 110.625 13.125 ;
        RECT 109.375 236.875 110.625 238.125 ;
        RECT 129.375 11.875 130.625 13.125 ;
      LAYER metal1 ;
        RECT 45.000 15.000 55.000 55.000 ;
        RECT 5.000 15.000 35.000 62.500 ;
        RECT 125.000 15.000 135.000 65.000 ;
        RECT 65.000 15.000 125.000 22.500 ;
        RECT 7.500 65.000 65.000 70.000 ;
        RECT 5.000 62.500 65.000 65.000 ;
        RECT 72.500 22.500 75.000 65.000 ;
        RECT 65.000 22.500 72.500 70.000 ;
        RECT 42.500 77.500 45.000 90.000 ;
        RECT 82.500 82.500 115.000 90.000 ;
        RECT 87.500 65.000 115.000 82.500 ;
        RECT 85.000 30.000 115.000 65.000 ;
        RECT 125.000 100.000 135.000 102.500 ;
        RECT 42.500 108.750 45.000 116.250 ;
        RECT 45.000 97.500 55.000 117.500 ;
        RECT 106.250 117.500 113.750 125.000 ;
        RECT 85.000 97.500 115.000 117.500 ;
        RECT 5.000 135.000 35.000 235.000 ;
        RECT 65.000 100.000 72.500 135.000 ;
        RECT 57.500 135.000 82.500 235.000 ;
        RECT 125.000 135.000 135.000 235.000 ;
  END 
END OAI22X1

MACRO OR2X1
  CLASS  CORE ;
  FOREIGN OR2X1 0.000 0.000 ;
  ORIGIN 0.000 0.000 ;
  SIZE 100.000 BY 250.000 ;
  SYMMETRY X Y  ;
  SITE core ;
  PIN A
    DIRECTION INPUT ;
    PORT
      LAYER metal1 ;
        RECT 5.000 82.500 15.000 92.500 ;
    END
  END A
  PIN B
    DIRECTION INPUT ;
    PORT
      LAYER metal1 ;
        RECT 25.000 82.500 55.000 92.500 ;
    END
  END B
  PIN gnd
    DIRECTION INOUT ;
    USE GROUND ;
    SHAPE ABUTMENT ;
    PORT
      LAYER metal1 ;
        RECT -5.000 -7.500 105.000 7.500 ;
    END
  END gnd
  PIN Y
    DIRECTION OUTPUT ;
    PORT
      LAYER metal1 ;
        RECT 85.000 107.500 95.000 117.500 ;
    END
  END Y
  PIN vdd
    DIRECTION INOUT ;
    USE POWER ;
    SHAPE ABUTMENT ;
    PORT
      LAYER metal1 ;
        RECT -5.000 242.500 105.000 257.500 ;
    END
  END vdd
  OBS
      LAYER metal1 ;
        RECT 9.375 236.875 10.625 238.125 ;
        RECT 29.375 11.875 30.625 13.125 ;
        RECT 29.375 236.875 30.625 238.125 ;
        RECT 49.375 11.875 50.625 13.125 ;
        RECT 49.375 111.875 50.625 113.125 ;
        RECT 49.375 236.875 50.625 238.125 ;
        RECT 69.375 86.875 70.625 88.125 ;
        RECT 69.375 136.875 70.625 138.125 ;
        RECT 69.375 161.875 70.625 163.125 ;
        RECT 69.375 186.875 70.625 188.125 ;
        RECT 69.375 211.875 70.625 213.125 ;
        RECT 69.375 236.875 70.625 238.125 ;
        RECT 89.375 11.875 90.625 13.125 ;
        RECT 89.375 186.875 90.625 188.125 ;
        RECT 89.375 211.875 90.625 213.125 ;
        RECT 89.375 236.875 90.625 238.125 ;
      LAYER metal1 ;
        RECT 5.000 15.000 15.000 40.000 ;
        RECT 65.000 15.000 75.000 40.000 ;
        RECT 6.250 67.500 13.750 75.000 ;
        RECT 5.000 47.500 15.000 67.500 ;
        RECT 62.500 72.500 65.000 82.500 ;
        RECT 27.500 72.500 62.500 75.000 ;
        RECT 87.500 40.000 95.000 100.000 ;
        RECT 85.000 15.000 95.000 40.000 ;
        RECT 27.500 40.000 55.000 60.000 ;
        RECT 25.000 15.000 55.000 40.000 ;
        RECT 15.000 120.000 67.500 127.500 ;
        RECT 67.500 90.000 72.500 127.500 ;
        RECT 75.000 60.000 80.000 97.500 ;
        RECT 72.500 60.000 75.000 117.500 ;
        RECT 72.500 117.500 77.500 127.500 ;
        RECT 55.000 52.500 80.000 60.000 ;
        RECT 5.000 120.000 15.000 235.000 ;
        RECT 57.500 135.000 67.500 235.000 ;
        RECT 77.500 185.000 80.000 235.000 ;
        RECT 80.000 177.500 87.500 235.000 ;
        RECT 87.500 125.000 95.000 185.000 ;
  END 
END OR2X1

MACRO OR2X2
  CLASS  CORE ;
  FOREIGN OR2X2 0.000 0.000 ;
  ORIGIN 0.000 0.000 ;
  SIZE 100.000 BY 250.000 ;
  SYMMETRY X Y  ;
  SITE core ;
  PIN A
    DIRECTION INPUT ;
    PORT
      LAYER metal1 ;
        RECT 25.000 57.500 35.000 67.500 ;
    END
  END A
  PIN B
    DIRECTION INPUT ;
    PORT
      LAYER metal1 ;
        RECT 25.000 82.500 55.000 92.500 ;
    END
  END B
  PIN gnd
    DIRECTION INOUT ;
    USE GROUND ;
    SHAPE ABUTMENT ;
    PORT
      LAYER metal1 ;
        RECT -5.000 -7.500 105.000 7.500 ;
    END
  END gnd
  PIN Y
    DIRECTION OUTPUT ;
    PORT
      LAYER metal1 ;
        RECT 85.000 107.500 95.000 117.500 ;
    END
  END Y
  PIN vdd
    DIRECTION INOUT ;
    USE POWER ;
    SHAPE ABUTMENT ;
    PORT
      LAYER metal1 ;
        RECT -5.000 242.500 105.000 257.500 ;
    END
  END vdd
  OBS
      LAYER metal1 ;
        RECT 9.375 86.875 10.625 88.125 ;
        RECT 9.375 111.875 10.625 113.125 ;
        RECT 9.375 236.875 10.625 238.125 ;
        RECT 29.375 11.875 30.625 13.125 ;
        RECT 29.375 236.875 30.625 238.125 ;
        RECT 49.375 11.875 50.625 13.125 ;
        RECT 49.375 111.875 50.625 113.125 ;
        RECT 49.375 236.875 50.625 238.125 ;
        RECT 69.375 61.875 70.625 63.125 ;
        RECT 69.375 136.875 70.625 138.125 ;
        RECT 69.375 161.875 70.625 163.125 ;
        RECT 69.375 186.875 70.625 188.125 ;
        RECT 69.375 211.875 70.625 213.125 ;
        RECT 69.375 236.875 70.625 238.125 ;
        RECT 89.375 11.875 90.625 13.125 ;
        RECT 89.375 161.875 90.625 163.125 ;
        RECT 89.375 186.875 90.625 188.125 ;
        RECT 89.375 211.875 90.625 213.125 ;
        RECT 89.375 236.875 90.625 238.125 ;
      LAYER metal1 ;
        RECT 5.000 15.000 15.000 40.000 ;
        RECT 65.000 15.000 75.000 60.000 ;
        RECT 5.000 47.500 15.000 67.500 ;
        RECT 15.000 58.750 17.500 66.250 ;
        RECT 87.500 65.000 95.000 100.000 ;
        RECT 85.000 15.000 95.000 65.000 ;
        RECT 50.000 100.000 60.000 102.500 ;
        RECT 15.000 120.000 67.500 127.500 ;
        RECT 67.500 112.500 70.000 127.500 ;
        RECT 75.000 75.000 77.500 122.500 ;
        RECT 70.000 75.000 75.000 127.500 ;
        RECT 47.500 40.000 55.000 67.500 ;
        RECT 47.500 67.500 77.500 75.000 ;
        RECT 25.000 15.000 55.000 40.000 ;
        RECT 5.000 120.000 15.000 235.000 ;
        RECT 57.500 135.000 67.500 235.000 ;
        RECT 77.500 135.000 87.500 235.000 ;
        RECT 87.500 125.000 95.000 142.500 ;
  END 
END OR2X2

MACRO TBUFX1
  CLASS  CORE ;
  FOREIGN TBUFX1 0.000 0.000 ;
  ORIGIN 0.000 0.000 ;
  SIZE 100.000 BY 250.000 ;
  SYMMETRY X Y  ;
  SITE core ;
  PIN A
    DIRECTION INPUT ;
    PORT
      LAYER metal1 ;
        RECT 85.000 107.500 95.000 117.500 ;
    END
  END A
  PIN EN
    DIRECTION INPUT ;
    PORT
      LAYER metal1 ;
        RECT 5.000 132.500 15.000 142.500 ;
    END
  END EN
  PIN gnd
    DIRECTION INOUT ;
    USE GROUND ;
    SHAPE ABUTMENT ;
    PORT
      LAYER metal1 ;
        RECT -5.000 -7.500 105.000 7.500 ;
    END
  END gnd
  PIN Y
    DIRECTION OUTPUT ;
    PORT
      LAYER metal1 ;
        RECT 45.000 107.500 55.000 117.500 ;
    END
  END Y
  PIN vdd
    DIRECTION INOUT ;
    USE POWER ;
    SHAPE ABUTMENT ;
    PORT
      LAYER metal1 ;
        RECT -5.000 242.500 105.000 257.500 ;
    END
  END vdd
  OBS
      LAYER metal1 ;
        RECT 29.375 11.875 30.625 13.125 ;
        RECT 29.375 61.875 30.625 63.125 ;
        RECT 29.375 86.875 30.625 88.125 ;
        RECT 29.375 161.875 30.625 163.125 ;
        RECT 29.375 236.875 30.625 238.125 ;
        RECT 49.375 11.875 50.625 13.125 ;
        RECT 49.375 236.875 50.625 238.125 ;
        RECT 69.375 11.875 70.625 13.125 ;
        RECT 69.375 61.875 70.625 63.125 ;
        RECT 69.375 86.875 70.625 88.125 ;
        RECT 69.375 111.875 70.625 113.125 ;
        RECT 69.375 136.875 70.625 138.125 ;
        RECT 69.375 236.875 70.625 238.125 ;
      LAYER metal1 ;
        RECT 5.000 15.000 15.000 40.000 ;
        RECT 80.000 15.000 90.000 65.000 ;
        RECT 50.000 65.000 57.500 100.000 ;
        RECT 47.500 15.000 57.500 65.000 ;
        RECT 86.250 92.500 93.750 100.000 ;
        RECT 75.000 82.500 95.000 92.500 ;
        RECT 5.000 157.500 25.000 167.500 ;
        RECT 6.250 150.000 13.750 157.500 ;
        RECT 5.000 185.000 15.000 235.000 ;
        RECT 30.000 92.500 40.000 100.000 ;
        RECT 30.000 100.000 37.500 125.000 ;
        RECT 32.500 40.000 40.000 92.500 ;
        RECT 40.000 82.500 42.500 92.500 ;
        RECT 25.000 15.000 35.000 30.000 ;
        RECT 25.000 30.000 40.000 40.000 ;
        RECT 25.000 185.000 40.000 192.500 ;
        RECT 25.000 192.500 35.000 235.000 ;
        RECT 32.500 132.500 40.000 185.000 ;
        RECT 30.000 125.000 40.000 132.500 ;
        RECT 47.500 135.000 50.000 235.000 ;
        RECT 50.000 125.000 57.500 235.000 ;
        RECT 80.000 135.000 90.000 235.000 ;
  END 
END TBUFX1

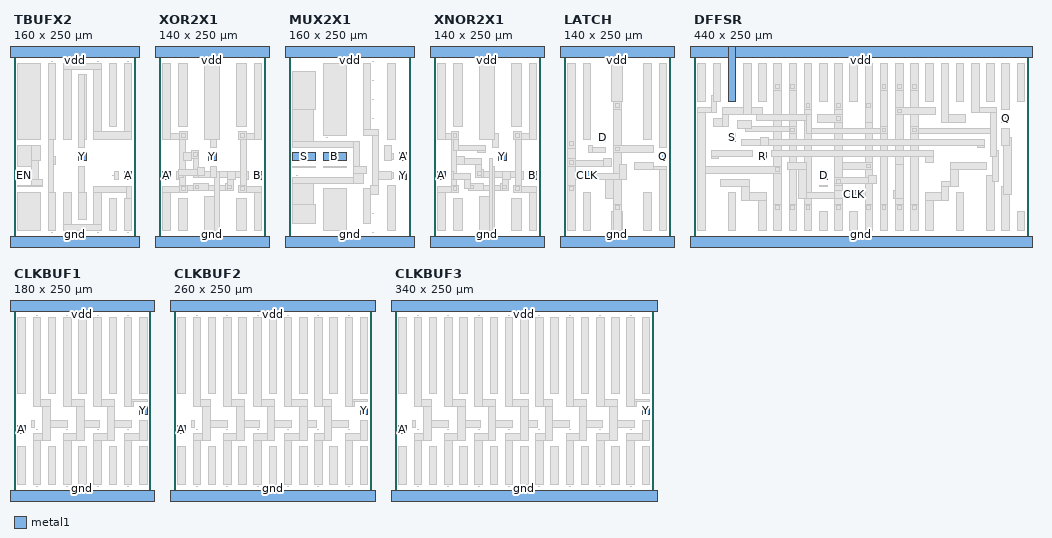
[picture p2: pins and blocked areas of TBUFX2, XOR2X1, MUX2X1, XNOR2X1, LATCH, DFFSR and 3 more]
MACRO TBUFX2
  CLASS  CORE ;
  FOREIGN TBUFX2 0.000 0.000 ;
  ORIGIN 0.000 0.000 ;
  SIZE 160.000 BY 250.000 ;
  SYMMETRY X Y  ;
  SITE core ;
  PIN A
    DIRECTION INPUT ;
    PORT
      LAYER metal1 ;
        RECT 145.000 82.500 155.000 92.500 ;
    END
  END A
  PIN EN
    DIRECTION INPUT ;
    PORT
      LAYER metal1 ;
        RECT 5.000 82.500 15.000 92.500 ;
    END
  END EN
  PIN gnd
    DIRECTION INOUT ;
    USE GROUND ;
    SHAPE ABUTMENT ;
    PORT
      LAYER metal1 ;
        RECT -5.000 -7.500 165.000 7.500 ;
    END
  END gnd
  PIN Y
    DIRECTION OUTPUT ;
    PORT
      LAYER metal1 ;
        RECT 85.000 107.500 95.000 117.500 ;
    END
  END Y
  PIN vdd
    DIRECTION INOUT ;
    USE POWER ;
    SHAPE ABUTMENT ;
    PORT
      LAYER metal1 ;
        RECT -5.000 242.500 165.000 257.500 ;
    END
  END vdd
  OBS
      LAYER metal1 ;
        RECT 49.375 11.875 50.625 13.125 ;
        RECT 49.375 236.875 50.625 238.125 ;
        RECT 69.375 11.875 70.625 13.125 ;
        RECT 69.375 236.875 70.625 238.125 ;
        RECT 89.375 11.875 90.625 13.125 ;
        RECT 89.375 236.875 90.625 238.125 ;
        RECT 109.375 11.875 110.625 13.125 ;
        RECT 109.375 236.875 110.625 238.125 ;
        RECT 129.375 86.875 130.625 88.125 ;
        RECT 149.375 11.875 150.625 13.125 ;
        RECT 149.375 236.875 150.625 238.125 ;
      LAYER metal1 ;
        RECT 125.000 15.000 135.000 57.500 ;
        RECT 5.000 15.000 35.000 65.000 ;
        RECT 65.000 22.500 75.000 65.000 ;
        RECT 105.000 22.500 115.000 65.000 ;
        RECT 65.000 15.000 115.000 22.500 ;
        RECT 105.000 65.000 147.500 72.500 ;
        RECT 147.500 57.500 155.000 72.500 ;
        RECT 145.000 15.000 155.000 57.500 ;
        RECT 132.500 82.500 137.500 92.500 ;
        RECT 85.000 30.000 95.000 65.000 ;
        RECT 85.000 65.000 92.500 100.000 ;
        RECT 5.000 100.000 22.500 127.500 ;
        RECT 22.500 75.000 37.500 82.500 ;
        RECT 22.500 82.500 32.500 107.500 ;
        RECT 22.500 107.500 35.000 127.500 ;
        RECT 5.000 72.500 37.500 75.000 ;
        RECT 85.000 125.000 92.500 220.000 ;
        RECT 92.500 135.000 95.000 220.000 ;
        RECT 5.000 135.000 35.000 235.000 ;
        RECT 52.500 102.500 55.000 112.500 ;
        RECT 45.000 15.000 55.000 65.000 ;
        RECT 45.000 65.000 52.500 135.000 ;
        RECT 45.000 135.000 55.000 235.000 ;
        RECT 125.000 152.500 135.000 235.000 ;
        RECT 65.000 135.000 75.000 227.500 ;
        RECT 65.000 227.500 115.000 235.000 ;
        RECT 105.000 145.000 115.000 227.500 ;
        RECT 145.000 145.000 155.000 235.000 ;
        RECT 105.000 135.000 155.000 145.000 ;
  END 
END TBUFX2

MACRO XOR2X1
  CLASS  CORE ;
  FOREIGN XOR2X1 0.000 0.000 ;
  ORIGIN 0.000 0.000 ;
  SIZE 140.000 BY 250.000 ;
  SYMMETRY X Y  ;
  SITE core ;
  PIN A
    DIRECTION INPUT ;
    PORT
      LAYER metal1 ;
        RECT 5.000 82.500 15.000 92.500 ;
    END
  END A
  PIN B
    DIRECTION INPUT ;
    PORT
      LAYER metal1 ;
        RECT 125.000 82.500 135.000 92.500 ;
    END
  END B
  PIN gnd
    DIRECTION INOUT ;
    USE GROUND ;
    SHAPE ABUTMENT ;
    PORT
      LAYER metal1 ;
        RECT -5.000 -7.500 145.000 7.500 ;
    END
  END gnd
  PIN Y
    DIRECTION OUTPUT ;
    PORT
      LAYER metal1 ;
        RECT 65.000 107.500 75.000 117.500 ;
    END
  END Y
  PIN vdd
    DIRECTION INOUT ;
    USE POWER ;
    SHAPE ABUTMENT ;
    PORT
      LAYER metal1 ;
        RECT -5.000 242.500 145.000 257.500 ;
    END
  END vdd
  OBS 
      LAYER metal2 ;
        RECT 27.500 65.000 37.500 75.000 ;
        RECT 27.500 67.500 97.500 75.000 ;
        RECT 45.000 67.500 55.000 77.500 ;
        RECT 87.500 67.500 97.500 77.500 ;
        RECT 27.500 65.000 35.000 145.000 ;
        RECT 27.500 135.000 37.500 145.000 ;
        RECT 105.000 65.000 115.000 75.000 ;
        RECT 45.000 85.000 115.000 92.500 ;
        RECT 45.000 85.000 52.500 120.000 ;
        RECT 42.500 110.000 52.500 120.000 ;
        RECT 107.500 65.000 115.000 145.000 ;
        RECT 105.000 135.000 115.000 145.000 ;
      LAYER metal1 ;
        RECT 25.000 152.500 37.500 235.000 ;
        RECT 5.000 135.000 37.500 142.500 ;
        RECT 27.500 135.000 37.500 145.000 ;
        RECT 5.000 135.000 15.000 235.000 ;
        RECT 5.000 15.000 15.000 72.500 ;
        RECT 5.000 65.000 37.500 72.500 ;
        RECT 27.500 65.000 37.500 75.000 ;
        RECT 25.000 15.000 37.500 57.500 ;
        RECT 32.500 107.500 42.500 117.500 ;
        RECT 42.500 110.000 52.500 120.000 ;
        RECT 22.500 85.000 32.500 92.500 ;
        RECT 22.500 82.500 25.000 92.500 ;
        RECT 25.000 87.500 60.000 95.000 ;
        RECT 50.000 87.500 60.000 97.500 ;
        RECT 45.000 67.500 65.000 77.500 ;
        RECT 67.500 125.000 75.000 235.000 ;
        RECT 60.000 135.000 80.000 235.000 ;
        RECT 60.000 15.000 80.000 60.000 ;
        RECT 72.500 15.000 80.000 92.500 ;
        RECT 67.500 85.000 75.000 100.000 ;
        RECT 87.500 67.500 97.500 77.500 ;
        RECT 90.000 67.500 97.500 92.500 ;
        RECT 90.000 82.500 100.000 92.500 ;
        RECT 102.500 152.500 115.000 235.000 ;
        RECT 102.500 15.000 115.000 57.500 ;
        RECT 115.000 82.500 117.500 92.500 ;
        RECT 105.000 135.000 135.000 142.500 ;
        RECT 105.000 135.000 115.000 145.000 ;
        RECT 125.000 135.000 135.000 235.000 ;
        RECT 125.000 15.000 135.000 72.500 ;
        RECT 105.000 65.000 135.000 72.500 ;
        RECT 105.000 65.000 115.000 75.000 ;
      LAYER via ;
        RECT 30.000 137.500 35.000 142.500 ;
        RECT 30.000 67.500 35.000 72.500 ;
        RECT 45.000 112.500 50.000 117.500 ;
        RECT 47.500 70.000 52.500 75.000 ;
        RECT 90.000 70.000 95.000 75.000 ;
        RECT 107.500 137.500 112.500 142.500 ;
        RECT 107.500 67.500 112.500 72.500 ;
  END 
END XOR2X1

MACRO MUX2X1
  CLASS  CORE ;
  FOREIGN MUX2X1 0.000 0.000 ;
  ORIGIN 0.000 0.000 ;
  SIZE 160.000 BY 250.000 ;
  SYMMETRY X Y  ;
  SITE core ;
  PIN A
    DIRECTION INPUT ;
    PORT
      LAYER metal1 ;
        RECT 145.000 107.500 155.000 117.500 ;
    END
  END A
  PIN B
    DIRECTION INPUT ;
    PORT
      LAYER metal1 ;
        RECT 45.000 107.500 75.000 117.500 ;
    END
  END B
  PIN S
    DIRECTION INPUT ;
    PORT
      LAYER metal1 ;
        RECT 5.000 107.500 35.000 117.500 ;
    END
  END S
  PIN gnd
    DIRECTION INOUT ;
    USE GROUND ;
    SHAPE ABUTMENT ;
    PORT
      LAYER metal1 ;
        RECT -5.000 -7.500 165.000 7.500 ;
    END
  END gnd
  PIN Y
    DIRECTION OUTPUT ;
    PORT
      LAYER metal1 ;
        RECT 145.000 82.500 155.000 92.500 ;
    END
  END Y
  PIN vdd
    DIRECTION INOUT ;
    USE POWER ;
    SHAPE ABUTMENT ;
    PORT
      LAYER metal1 ;
        RECT -5.000 242.500 165.000 257.500 ;
    END
  END vdd
  OBS
      LAYER metal1 ;
        RECT 9.375 86.875 10.625 88.125 ;
        RECT 49.375 136.875 50.625 138.125 ;
        RECT 89.375 11.875 90.625 13.125 ;
        RECT 89.375 236.875 90.625 238.125 ;
        RECT 109.375 11.875 110.625 13.125 ;
        RECT 109.375 36.875 110.625 38.125 ;
        RECT 109.375 161.875 110.625 163.125 ;
        RECT 109.375 186.875 110.625 188.125 ;
        RECT 109.375 211.875 110.625 213.125 ;
        RECT 109.375 236.875 110.625 238.125 ;
      LAYER metal1 ;
        RECT 45.000 15.000 75.000 70.000 ;
        RECT 130.000 15.000 140.000 75.000 ;
        RECT 5.000 97.500 35.000 100.000 ;
        RECT 45.000 97.500 75.000 100.000 ;
        RECT 135.000 108.750 137.500 116.250 ;
        RECT 125.000 107.500 135.000 127.500 ;
        RECT 5.000 125.000 85.000 132.500 ;
        RECT 5.000 132.500 32.500 175.000 ;
        RECT 5.000 175.000 35.000 225.000 ;
        RECT 5.000 25.000 35.000 50.000 ;
        RECT 5.000 50.000 32.500 77.500 ;
        RECT 85.000 77.500 97.500 90.000 ;
        RECT 5.000 77.500 85.000 85.000 ;
        RECT 85.000 90.000 102.500 100.000 ;
        RECT 85.000 100.000 92.500 132.500 ;
        RECT 45.000 140.000 75.000 235.000 ;
        RECT 135.000 83.750 137.500 91.250 ;
        RECT 117.500 82.500 135.000 92.500 ;
        RECT 97.500 140.000 117.500 147.500 ;
        RECT 110.000 75.000 117.500 140.000 ;
        RECT 107.500 62.500 117.500 75.000 ;
        RECT 97.500 147.500 107.500 235.000 ;
        RECT 97.500 25.000 107.500 70.000 ;
        RECT 130.000 135.000 140.000 235.000 ;
  END 
END MUX2X1

MACRO XNOR2X1
  CLASS  CORE ;
  FOREIGN XNOR2X1 0.000 0.000 ;
  ORIGIN 0.000 0.000 ;
  SIZE 140.000 BY 250.000 ;
  SYMMETRY X Y  ;
  SITE core ;
  PIN A
    DIRECTION INPUT ;
    PORT
      LAYER metal1 ;
        RECT 5.000 82.500 15.000 92.500 ;
    END
  END A
  PIN B
    DIRECTION INPUT ;
    PORT
      LAYER metal1 ;
        RECT 125.000 82.500 135.000 92.500 ;
    END
  END B
  PIN gnd
    DIRECTION INOUT ;
    USE GROUND ;
    SHAPE ABUTMENT ;
    PORT
      LAYER metal1 ;
        RECT -5.000 -7.500 145.000 7.500 ;
    END
  END gnd
  PIN Y
    DIRECTION OUTPUT ;
    PORT
      LAYER metal1 ;
        RECT 85.000 107.500 95.000 117.500 ;
    END
  END Y
  PIN vdd
    DIRECTION INOUT ;
    USE POWER ;
    SHAPE ABUTMENT ;
    PORT
      LAYER metal1 ;
        RECT -5.000 242.500 145.000 257.500 ;
    END
  END vdd
  OBS 
      LAYER metal2 ;
        RECT 22.500 65.000 32.500 75.000 ;
        RECT 22.500 65.000 30.000 145.000 ;
        RECT 22.500 135.000 32.500 145.000 ;
        RECT 45.000 67.500 97.500 75.000 ;
        RECT 45.000 67.500 55.000 77.500 ;
        RECT 87.500 67.500 97.500 77.500 ;
        RECT 105.000 65.000 115.000 75.000 ;
        RECT 55.000 85.000 115.000 92.500 ;
        RECT 55.000 85.000 65.000 95.000 ;
        RECT 107.500 65.000 115.000 145.000 ;
        RECT 105.000 135.000 115.000 145.000 ;
      LAYER metal1 ;
        RECT 5.000 15.000 15.000 72.500 ;
        RECT 5.000 65.000 32.500 72.500 ;
        RECT 22.500 65.000 32.500 75.000 ;
        RECT 25.000 152.500 37.500 235.000 ;
        RECT 25.000 15.000 37.500 57.500 ;
        RECT 55.000 85.000 65.000 95.000 ;
        RECT 55.000 85.000 62.500 110.000 ;
        RECT 30.000 102.500 62.500 110.000 ;
        RECT 30.000 102.500 40.000 112.500 ;
        RECT 45.000 67.500 65.000 77.500 ;
        RECT 40.000 70.000 47.500 90.000 ;
        RECT 22.500 82.500 47.500 90.000 ;
        RECT 22.500 82.500 25.000 92.500 ;
        RECT 57.500 117.500 67.500 127.500 ;
        RECT 25.000 120.000 67.500 127.500 ;
        RECT 5.000 135.000 32.500 142.500 ;
        RECT 25.000 120.000 32.500 145.000 ;
        RECT 22.500 135.000 32.500 145.000 ;
        RECT 5.000 135.000 15.000 235.000 ;
        RECT 60.000 15.000 80.000 60.000 ;
        RECT 72.500 15.000 80.000 100.000 ;
        RECT 72.500 15.000 77.500 110.000 ;
        RECT 77.500 125.000 85.000 142.500 ;
        RECT 60.000 135.000 80.000 235.000 ;
        RECT 87.500 67.500 97.500 77.500 ;
        RECT 90.000 67.500 97.500 92.500 ;
        RECT 90.000 82.500 100.000 92.500 ;
        RECT 102.500 152.500 115.000 235.000 ;
        RECT 102.500 15.000 115.000 57.500 ;
        RECT 115.000 82.500 117.500 92.500 ;
        RECT 105.000 135.000 135.000 142.500 ;
        RECT 105.000 135.000 115.000 145.000 ;
        RECT 125.000 135.000 135.000 235.000 ;
        RECT 125.000 15.000 135.000 72.500 ;
        RECT 105.000 65.000 135.000 72.500 ;
        RECT 105.000 65.000 115.000 75.000 ;
      LAYER via ;
        RECT 25.000 137.500 30.000 142.500 ;
        RECT 25.000 67.500 30.000 72.500 ;
        RECT 47.500 70.000 52.500 75.000 ;
        RECT 57.500 87.500 62.500 92.500 ;
        RECT 90.000 70.000 95.000 75.000 ;
        RECT 107.500 137.500 112.500 142.500 ;
        RECT 107.500 67.500 112.500 72.500 ;
  END 
END XNOR2X1

MACRO LATCH
  CLASS  CORE ;
  FOREIGN LATCH 0.000 0.000 ;
  ORIGIN 0.000 0.000 ;
  SIZE 140.000 BY 250.000 ;
  SYMMETRY X Y  ;
  SITE core ;
  PIN Q
    DIRECTION OUTPUT ;
    PORT
      LAYER metal1 ;
        RECT 125.000 107.500 135.000 117.500 ;
    END
  END Q
  PIN CLK
    DIRECTION INPUT ;
    PORT
      LAYER metal1 ;
        RECT 25.000 82.500 35.000 92.500 ;
    END
  END CLK
  PIN D
    DIRECTION INPUT ;
    PORT
      LAYER metal1 ;
        RECT 45.000 132.500 55.000 142.500 ;
    END
  END D
  PIN gnd
    DIRECTION INOUT ;
    USE GROUND ;
    SHAPE ABUTMENT ;
    PORT
      LAYER metal1 ;
        RECT -5.000 -7.500 145.000 7.500 ;
    END
  END gnd
  PIN vdd
    DIRECTION INOUT ;
    USE POWER ;
    SHAPE ABUTMENT ;
    PORT
      LAYER metal1 ;
        RECT -5.000 242.500 145.000 257.500 ;
    END
  END vdd
  OBS 
      LAYER metal2 ;
        RECT 5.000 65.000 15.000 135.000 ;
        RECT 65.000 40.000 75.000 185.000 ;
      LAYER metal1 ;
        RECT 5.000 122.500 15.000 235.000 ;
        RECT 5.000 15.000 15.000 75.000 ;
        RECT 15.000 82.500 17.500 92.500 ;
        RECT 25.000 135.000 35.000 235.000 ;
        RECT 25.000 15.000 35.000 65.000 ;
        RECT 32.500 117.500 55.000 125.000 ;
        RECT 32.500 117.500 37.500 127.500 ;
        RECT 5.000 100.000 62.500 107.500 ;
        RECT 5.000 100.000 15.000 110.000 ;
        RECT 52.500 100.000 62.500 110.000 ;
        RECT 65.000 175.000 75.000 235.000 ;
        RECT 62.500 185.000 77.500 235.000 ;
        RECT 62.500 15.000 77.500 40.000 ;
        RECT 65.000 15.000 75.000 50.000 ;
        RECT 55.000 57.500 65.000 90.000 ;
        RECT 42.500 82.500 82.500 90.000 ;
        RECT 72.500 82.500 82.500 102.500 ;
        RECT 105.000 135.000 115.000 235.000 ;
        RECT 105.000 15.000 115.000 65.000 ;
        RECT 65.000 117.500 117.500 127.500 ;
        RECT 125.000 125.000 135.000 235.000 ;
        RECT 125.000 15.000 135.000 100.000 ;
        RECT 92.500 95.000 135.000 100.000 ;
        RECT 92.500 95.000 117.500 105.000 ;
      LAYER via ;
        RECT 7.500 127.500 12.500 132.500 ;
        RECT 7.500 102.500 12.500 107.500 ;
        RECT 7.500 67.500 12.500 72.500 ;
        RECT 67.500 177.500 72.500 182.500 ;
        RECT 67.500 120.000 72.500 125.000 ;
        RECT 67.500 42.500 72.500 47.500 ;
  END 
END LATCH

MACRO DFFSR
  CLASS  CORE ;
  FOREIGN DFFSR 0.000 0.000 ;
  ORIGIN 0.000 0.000 ;
  SIZE 440.000 BY 250.000 ;
  SYMMETRY X Y  ;
  SITE core ;
  PIN Q
    DIRECTION OUTPUT ;
    PORT
      LAYER metal1 ;
        RECT 405.000 157.500 415.000 167.500 ;
    END
  END Q
  PIN CLK
    DIRECTION INPUT ;
    PORT
      LAYER metal1 ;
        RECT 205.000 57.500 215.000 67.500 ;
    END
  END CLK
  PIN R
    DIRECTION INPUT ;
    PORT
      LAYER metal1 ;
        RECT 85.000 107.500 95.000 117.500 ;
    END
  END R
  PIN S
    DIRECTION INPUT ;
    PORT
      LAYER metal1 ;
        RECT 45.000 132.500 55.000 142.500 ;
    END
  END S
  PIN D
    DIRECTION INPUT ;
    PORT
      LAYER metal1 ;
        RECT 165.000 82.500 175.000 92.500 ;
    END
  END D
  PIN gnd
    DIRECTION INOUT ;
    USE GROUND ;
    SHAPE ABUTMENT ;
    PORT
      LAYER metal1 ;
        RECT -5.000 -7.500 445.000 7.500 ;
    END
  END gnd
  PIN vdd
    DIRECTION INOUT ;
    USE POWER ;
    SHAPE ABUTMENT ;
    PORT
      LAYER metal1 ;
        RECT -5.000 242.500 445.000 257.500 ;
        RECT 45.000 185.000 55.000 257.500 ;
    END
  END vdd
  OBS 
      LAYER metal2 ;
        RECT 105.000 40.000 115.000 210.000 ;
        RECT 125.000 40.000 135.000 210.000 ;
        RECT 145.000 40.000 155.000 185.000 ;
        RECT 185.000 40.000 195.000 185.000 ;
        RECT 225.000 40.000 235.000 185.000 ;
        RECT 245.000 40.000 255.000 210.000 ;
        RECT 265.000 40.000 275.000 210.000 ;
        RECT 285.000 40.000 295.000 210.000 ;
      LAYER metal1 ;
        RECT 5.000 185.000 15.000 235.000 ;
        RECT 45.000 15.000 55.000 65.000 ;
        RECT 22.500 110.000 32.500 120.000 ;
        RECT 22.500 112.500 77.500 120.000 ;
        RECT 85.000 185.000 95.000 235.000 ;
        RECT 85.000 15.000 95.000 65.000 ;
        RECT 62.500 55.000 95.000 65.000 ;
        RECT 62.500 55.000 72.500 82.500 ;
        RECT 35.000 72.500 72.500 82.500 ;
        RECT 105.000 200.000 115.000 235.000 ;
        RECT 5.000 90.000 115.000 100.000 ;
        RECT 5.000 15.000 15.000 177.500 ;
        RECT 5.000 170.000 30.000 177.500 ;
        RECT 22.500 170.000 30.000 192.500 ;
        RECT 25.000 185.000 35.000 235.000 ;
        RECT 105.000 15.000 115.000 50.000 ;
        RECT 125.000 200.000 135.000 235.000 ;
        RECT 67.500 145.000 135.000 152.500 ;
        RECT 125.000 142.500 135.000 152.500 ;
        RECT 57.500 150.000 75.000 160.000 ;
        RECT 125.000 15.000 135.000 50.000 ;
        RECT 145.000 175.000 155.000 235.000 ;
        RECT 145.000 15.000 155.000 50.000 ;
        RECT 165.000 185.000 175.000 235.000 ;
        RECT 165.000 72.500 175.000 75.000 ;
        RECT 165.000 15.000 175.000 40.000 ;
        RECT 185.000 175.000 195.000 235.000 ;
        RECT 162.500 157.500 195.000 167.500 ;
        RECT 137.500 57.500 195.000 65.000 ;
        RECT 185.000 57.500 195.000 67.500 ;
        RECT 137.500 57.500 147.500 105.000 ;
        RECT 122.500 95.000 147.500 105.000 ;
        RECT 185.000 15.000 195.000 50.000 ;
        RECT 205.000 185.000 215.000 235.000 ;
        RECT 205.000 15.000 215.000 40.000 ;
        RECT 222.500 57.500 225.000 67.500 ;
        RECT 225.000 157.500 235.000 235.000 ;
        RECT 195.000 95.000 235.000 105.000 ;
        RECT 225.000 15.000 235.000 50.000 ;
        RECT 185.000 75.000 195.000 85.000 ;
        RECT 185.000 77.500 240.000 85.000 ;
        RECT 230.000 77.500 240.000 87.500 ;
        RECT 245.000 200.000 255.000 235.000 ;
        RECT 147.500 142.500 255.000 150.000 ;
        RECT 245.000 142.500 255.000 152.500 ;
        RECT 25.000 152.500 45.000 162.500 ;
        RECT 37.500 152.500 45.000 177.500 ;
        RECT 82.500 160.000 155.000 167.500 ;
        RECT 147.500 142.500 155.000 167.500 ;
        RECT 37.500 167.500 90.000 177.500 ;
        RECT 65.000 167.500 75.000 235.000 ;
        RECT 245.000 15.000 255.000 50.000 ;
        RECT 265.000 200.000 275.000 235.000 ;
        RECT 262.500 57.500 275.000 67.500 ;
        RECT 265.000 57.500 275.000 102.500 ;
        RECT 265.000 15.000 275.000 50.000 ;
        RECT 285.000 200.000 295.000 235.000 ;
        RECT 285.000 15.000 295.000 50.000 ;
        RECT 305.000 185.000 315.000 235.000 ;
        RECT 305.000 105.000 315.000 120.000 ;
        RECT 102.500 112.500 315.000 120.000 ;
        RECT 265.000 167.500 317.500 177.500 ;
        RECT 345.000 185.000 355.000 235.000 ;
        RECT 345.000 15.000 355.000 65.000 ;
        RECT 325.000 157.500 357.500 167.500 ;
        RECT 325.000 157.500 335.000 235.000 ;
        RECT 372.500 125.000 382.500 135.000 ;
        RECT 62.500 127.500 382.500 135.000 ;
        RECT 87.500 127.500 97.500 137.500 ;
        RECT 305.000 15.000 315.000 65.000 ;
        RECT 305.000 55.000 335.000 65.000 ;
        RECT 325.000 55.000 335.000 80.000 ;
        RECT 325.000 72.500 347.500 80.000 ;
        RECT 337.500 72.500 347.500 105.000 ;
        RECT 337.500 95.000 385.000 105.000 ;
        RECT 385.000 185.000 395.000 235.000 ;
        RECT 385.000 15.000 395.000 87.500 ;
        RECT 392.500 80.000 400.000 120.000 ;
        RECT 285.000 142.500 397.500 150.000 ;
        RECT 285.000 142.500 295.000 152.500 ;
        RECT 390.000 112.500 397.500 177.500 ;
        RECT 365.000 170.000 397.500 177.500 ;
        RECT 365.000 170.000 375.000 235.000 ;
        RECT 405.000 175.000 415.000 235.000 ;
        RECT 405.000 15.000 415.000 72.500 ;
        RECT 407.500 62.500 417.500 137.500 ;
        RECT 405.000 127.500 415.000 150.000 ;
        RECT 425.000 185.000 435.000 235.000 ;
        RECT 425.000 15.000 435.000 40.000 ;
      LAYER via ;
        RECT 107.500 202.500 112.500 207.500 ;
        RECT 107.500 92.500 112.500 97.500 ;
        RECT 107.500 42.500 112.500 47.500 ;
        RECT 127.500 202.500 132.500 207.500 ;
        RECT 127.500 145.000 132.500 150.000 ;
        RECT 127.500 42.500 132.500 47.500 ;
        RECT 147.500 177.500 152.500 182.500 ;
        RECT 147.500 42.500 152.500 47.500 ;
        RECT 187.500 177.500 192.500 182.500 ;
        RECT 187.500 160.000 192.500 165.000 ;
        RECT 187.500 77.500 192.500 82.500 ;
        RECT 187.500 42.500 192.500 47.500 ;
        RECT 227.500 177.500 232.500 182.500 ;
        RECT 227.500 97.500 232.500 102.500 ;
        RECT 227.500 42.500 232.500 47.500 ;
        RECT 247.500 202.500 252.500 207.500 ;
        RECT 247.500 145.000 252.500 150.000 ;
        RECT 247.500 42.500 252.500 47.500 ;
        RECT 267.500 202.500 272.500 207.500 ;
        RECT 267.500 170.000 272.500 175.000 ;
        RECT 267.500 42.500 272.500 47.500 ;
        RECT 287.500 202.500 292.500 207.500 ;
        RECT 287.500 145.000 292.500 150.000 ;
        RECT 287.500 42.500 292.500 47.500 ;
  END 
END DFFSR

MACRO CLKBUF1
  CLASS  CORE ;
  FOREIGN CLKBUF1 0.000 0.000 ;
  ORIGIN 0.000 0.000 ;
  SIZE 180.000 BY 250.000 ;
  SYMMETRY X Y  ;
  SITE core ;
  PIN A
    DIRECTION INPUT ;
    PORT
      LAYER metal1 ;
        RECT 5.000 82.500 15.000 92.500 ;
    END
  END A
  PIN gnd
    DIRECTION INOUT ;
    USE GROUND ;
    SHAPE ABUTMENT ;
    PORT
      LAYER metal1 ;
        RECT -5.000 -7.500 185.000 7.500 ;
    END
  END gnd
  PIN Y
    DIRECTION OUTPUT ;
    PORT
      LAYER metal1 ;
        RECT 165.000 107.500 175.000 117.500 ;
    END
  END Y
  PIN vdd
    DIRECTION INOUT ;
    USE POWER ;
    SHAPE ABUTMENT ;
    PORT
      LAYER metal1 ;
        RECT -5.000 242.500 185.000 257.500 ;
    END
  END vdd
  OBS 
      LAYER metal1 ;
        RECT 29.375 11.875 30.625 13.125 ;
        RECT 29.375 86.875 30.625 88.125 ;
        RECT 29.375 236.875 30.625 238.125 ;
        RECT 69.375 11.875 70.625 13.125 ;
        RECT 69.375 86.875 70.625 88.125 ;
        RECT 69.375 236.875 70.625 238.125 ;
        RECT 109.375 11.875 110.625 13.125 ;
        RECT 109.375 86.875 110.625 88.125 ;
        RECT 109.375 236.875 110.625 238.125 ;
        RECT 149.375 11.875 150.625 13.125 ;
        RECT 149.375 86.875 150.625 88.125 ;
        RECT 149.375 236.875 150.625 238.125 ;
      LAYER metal1 ;
        RECT 5.000 135.000 15.000 235.000 ;
        RECT 5.000 15.000 15.000 65.000 ;
        RECT 22.500 90.000 27.500 100.000 ;
        RECT 45.000 135.000 55.000 235.000 ;
        RECT 45.000 15.000 55.000 65.000 ;
        RECT 25.000 15.000 35.000 82.500 ;
        RECT 25.000 72.500 47.500 82.500 ;
        RECT 37.500 90.000 70.000 100.000 ;
        RECT 37.500 72.500 47.500 127.500 ;
        RECT 25.000 117.500 47.500 127.500 ;
        RECT 25.000 117.500 35.000 235.000 ;
        RECT 85.000 135.000 95.000 235.000 ;
        RECT 85.000 15.000 95.000 65.000 ;
        RECT 65.000 15.000 75.000 82.500 ;
        RECT 65.000 72.500 92.500 82.500 ;
        RECT 82.500 90.000 112.500 100.000 ;
        RECT 82.500 72.500 92.500 127.500 ;
        RECT 65.000 117.500 92.500 127.500 ;
        RECT 65.000 117.500 75.000 235.000 ;
        RECT 125.000 135.000 135.000 235.000 ;
        RECT 125.000 15.000 135.000 65.000 ;
        RECT 105.000 15.000 115.000 82.500 ;
        RECT 105.000 72.500 132.500 82.500 ;
        RECT 122.500 90.000 155.000 100.000 ;
        RECT 122.500 72.500 132.500 127.500 ;
        RECT 105.000 117.500 132.500 127.500 ;
        RECT 105.000 117.500 115.000 235.000 ;
        RECT 165.000 135.000 175.000 235.000 ;
        RECT 145.000 117.500 157.500 127.500 ;
        RECT 145.000 125.000 175.000 127.500 ;
        RECT 145.000 117.500 155.000 235.000 ;
        RECT 145.000 15.000 155.000 82.500 ;
        RECT 145.000 72.500 175.000 82.500 ;
        RECT 165.000 72.500 175.000 100.000 ;
        RECT 165.000 15.000 175.000 65.000 ;
  END 
END CLKBUF1

MACRO CLKBUF2
  CLASS  CORE ;
  FOREIGN CLKBUF2 0.000 0.000 ;
  ORIGIN 0.000 0.000 ;
  SIZE 260.000 BY 250.000 ;
  SYMMETRY X Y  ;
  SITE core ;
  PIN A
    DIRECTION INPUT ;
    PORT
      LAYER metal1 ;
        RECT 5.000 82.500 15.000 92.500 ;
    END
  END A
  PIN gnd
    DIRECTION INOUT ;
    USE GROUND ;
    SHAPE ABUTMENT ;
    PORT
      LAYER metal1 ;
        RECT -5.000 -7.500 265.000 7.500 ;
    END
  END gnd
  PIN Y
    DIRECTION OUTPUT ;
    PORT
      LAYER metal1 ;
        RECT 245.000 107.500 255.000 117.500 ;
    END
  END Y
  PIN vdd
    DIRECTION INOUT ;
    USE POWER ;
    SHAPE ABUTMENT ;
    PORT
      LAYER metal1 ;
        RECT -5.000 242.500 265.000 257.500 ;
    END
  END vdd
  OBS 
      LAYER metal1 ;
        RECT 29.375 11.875 30.625 13.125 ;
        RECT 29.375 86.875 30.625 88.125 ;
        RECT 29.375 236.875 30.625 238.125 ;
        RECT 69.375 11.875 70.625 13.125 ;
        RECT 69.375 86.875 70.625 88.125 ;
        RECT 69.375 236.875 70.625 238.125 ;
        RECT 109.375 11.875 110.625 13.125 ;
        RECT 109.375 86.875 110.625 88.125 ;
        RECT 109.375 236.875 110.625 238.125 ;
        RECT 149.375 11.875 150.625 13.125 ;
        RECT 149.375 86.875 150.625 88.125 ;
        RECT 149.375 236.875 150.625 238.125 ;
        RECT 189.375 11.875 190.625 13.125 ;
        RECT 189.375 86.875 190.625 88.125 ;
        RECT 189.375 236.875 190.625 238.125 ;
        RECT 229.375 11.875 230.625 13.125 ;
        RECT 229.375 86.875 230.625 88.125 ;
        RECT 229.375 236.875 230.625 238.125 ;
      LAYER metal1 ;
        RECT 5.000 135.000 15.000 235.000 ;
        RECT 5.000 15.000 15.000 65.000 ;
        RECT 22.500 90.000 27.500 100.000 ;
        RECT 45.000 135.000 55.000 235.000 ;
        RECT 45.000 15.000 55.000 65.000 ;
        RECT 25.000 15.000 35.000 82.500 ;
        RECT 25.000 72.500 47.500 82.500 ;
        RECT 37.500 90.000 70.000 100.000 ;
        RECT 37.500 72.500 47.500 127.500 ;
        RECT 25.000 117.500 47.500 127.500 ;
        RECT 25.000 117.500 35.000 235.000 ;
        RECT 85.000 135.000 95.000 235.000 ;
        RECT 85.000 15.000 95.000 65.000 ;
        RECT 65.000 15.000 75.000 82.500 ;
        RECT 65.000 72.500 92.500 82.500 ;
        RECT 82.500 90.000 112.500 100.000 ;
        RECT 82.500 72.500 92.500 127.500 ;
        RECT 65.000 117.500 92.500 127.500 ;
        RECT 65.000 117.500 75.000 235.000 ;
        RECT 125.000 135.000 135.000 235.000 ;
        RECT 125.000 15.000 135.000 65.000 ;
        RECT 105.000 15.000 115.000 82.500 ;
        RECT 105.000 72.500 132.500 82.500 ;
        RECT 122.500 90.000 155.000 100.000 ;
        RECT 122.500 72.500 132.500 127.500 ;
        RECT 105.000 117.500 132.500 127.500 ;
        RECT 105.000 117.500 115.000 235.000 ;
        RECT 165.000 135.000 175.000 235.000 ;
        RECT 165.000 15.000 175.000 65.000 ;
        RECT 145.000 15.000 155.000 82.500 ;
        RECT 145.000 72.500 175.000 82.500 ;
        RECT 165.000 90.000 187.500 100.000 ;
        RECT 165.000 72.500 175.000 127.500 ;
        RECT 145.000 117.500 175.000 127.500 ;
        RECT 145.000 117.500 155.000 235.000 ;
        RECT 205.000 135.000 215.000 235.000 ;
        RECT 205.000 15.000 215.000 65.000 ;
        RECT 185.000 15.000 195.000 82.500 ;
        RECT 185.000 72.500 207.500 82.500 ;
        RECT 197.500 90.000 230.000 100.000 ;
        RECT 197.500 72.500 207.500 127.500 ;
        RECT 185.000 117.500 207.500 127.500 ;
        RECT 185.000 117.500 195.000 235.000 ;
        RECT 245.000 135.000 255.000 235.000 ;
        RECT 225.000 117.500 237.500 127.500 ;
        RECT 225.000 125.000 255.000 127.500 ;
        RECT 225.000 117.500 235.000 235.000 ;
        RECT 225.000 15.000 235.000 82.500 ;
        RECT 225.000 72.500 255.000 82.500 ;
        RECT 245.000 72.500 255.000 100.000 ;
        RECT 245.000 15.000 255.000 65.000 ;
  END 
END CLKBUF2

MACRO CLKBUF3
  CLASS  CORE ;
  FOREIGN CLKBUF3 0.000 0.000 ;
  ORIGIN 0.000 0.000 ;
  SIZE 340.000 BY 250.000 ;
  SYMMETRY X Y  ;
  SITE core ;
  PIN A
    DIRECTION INPUT ;
    PORT
      LAYER metal1 ;
        RECT 5.000 82.500 15.000 92.500 ;
    END
  END A
  PIN gnd
    DIRECTION INOUT ;
    USE GROUND ;
    SHAPE ABUTMENT ;
    PORT
      LAYER metal1 ;
        RECT -5.000 -7.500 345.000 7.500 ;
    END
  END gnd
  PIN Y
    DIRECTION OUTPUT ;
    PORT
      LAYER metal1 ;
        RECT 325.000 107.500 335.000 117.500 ;
    END
  END Y
  PIN vdd
    DIRECTION INOUT ;
    USE POWER ;
    SHAPE ABUTMENT ;
    PORT
      LAYER metal1 ;
        RECT -5.000 242.500 345.000 257.500 ;
    END
  END vdd
  OBS 
      LAYER metal1 ;
        RECT 29.375 11.875 30.625 13.125 ;
        RECT 29.375 86.875 30.625 88.125 ;
        RECT 29.375 236.875 30.625 238.125 ;
        RECT 69.375 11.875 70.625 13.125 ;
        RECT 69.375 86.875 70.625 88.125 ;
        RECT 69.375 236.875 70.625 238.125 ;
        RECT 109.375 11.875 110.625 13.125 ;
        RECT 109.375 86.875 110.625 88.125 ;
        RECT 109.375 236.875 110.625 238.125 ;
        RECT 149.375 11.875 150.625 13.125 ;
        RECT 149.375 86.875 150.625 88.125 ;
        RECT 149.375 236.875 150.625 238.125 ;
        RECT 189.375 11.875 190.625 13.125 ;
        RECT 189.375 86.875 190.625 88.125 ;
        RECT 189.375 236.875 190.625 238.125 ;
        RECT 229.375 11.875 230.625 13.125 ;
        RECT 229.375 86.875 230.625 88.125 ;
        RECT 229.375 236.875 230.625 238.125 ;
        RECT 269.375 11.875 270.625 13.125 ;
        RECT 269.375 86.875 270.625 88.125 ;
        RECT 269.375 236.875 270.625 238.125 ;
        RECT 309.375 11.875 310.625 13.125 ;
        RECT 309.375 86.875 310.625 88.125 ;
        RECT 309.375 236.875 310.625 238.125 ;
      LAYER metal1 ;
        RECT 5.000 135.000 15.000 235.000 ;
        RECT 5.000 15.000 15.000 65.000 ;
        RECT 22.500 90.000 27.500 100.000 ;
        RECT 45.000 135.000 55.000 235.000 ;
        RECT 45.000 15.000 55.000 65.000 ;
        RECT 25.000 15.000 35.000 82.500 ;
        RECT 25.000 72.500 47.500 82.500 ;
        RECT 37.500 90.000 70.000 100.000 ;
        RECT 37.500 72.500 47.500 127.500 ;
        RECT 25.000 117.500 47.500 127.500 ;
        RECT 25.000 117.500 35.000 235.000 ;
        RECT 85.000 135.000 95.000 235.000 ;
        RECT 85.000 15.000 95.000 65.000 ;
        RECT 65.000 15.000 75.000 82.500 ;
        RECT 65.000 72.500 92.500 82.500 ;
        RECT 82.500 90.000 112.500 100.000 ;
        RECT 82.500 72.500 92.500 127.500 ;
        RECT 65.000 117.500 92.500 127.500 ;
        RECT 65.000 117.500 75.000 235.000 ;
        RECT 125.000 135.000 135.000 235.000 ;
        RECT 125.000 15.000 135.000 65.000 ;
        RECT 105.000 15.000 115.000 82.500 ;
        RECT 105.000 72.500 132.500 82.500 ;
        RECT 122.500 90.000 155.000 100.000 ;
        RECT 122.500 72.500 132.500 127.500 ;
        RECT 105.000 117.500 132.500 127.500 ;
        RECT 105.000 117.500 115.000 235.000 ;
        RECT 165.000 135.000 175.000 235.000 ;
        RECT 165.000 15.000 175.000 65.000 ;
        RECT 145.000 15.000 155.000 82.500 ;
        RECT 145.000 72.500 175.000 82.500 ;
        RECT 165.000 90.000 187.500 100.000 ;
        RECT 165.000 72.500 175.000 127.500 ;
        RECT 145.000 117.500 175.000 127.500 ;
        RECT 145.000 117.500 155.000 235.000 ;
        RECT 205.000 135.000 215.000 235.000 ;
        RECT 205.000 15.000 215.000 65.000 ;
        RECT 185.000 15.000 195.000 82.500 ;
        RECT 185.000 72.500 207.500 82.500 ;
        RECT 197.500 90.000 230.000 100.000 ;
        RECT 197.500 72.500 207.500 127.500 ;
        RECT 185.000 117.500 207.500 127.500 ;
        RECT 185.000 117.500 195.000 235.000 ;
        RECT 245.000 135.000 255.000 235.000 ;
        RECT 245.000 15.000 255.000 65.000 ;
        RECT 225.000 15.000 235.000 82.500 ;
        RECT 225.000 72.500 252.500 82.500 ;
        RECT 242.500 90.000 272.500 100.000 ;
        RECT 242.500 72.500 252.500 127.500 ;
        RECT 225.000 117.500 252.500 127.500 ;
        RECT 225.000 117.500 235.000 235.000 ;
        RECT 285.000 135.000 295.000 235.000 ;
        RECT 285.000 15.000 295.000 65.000 ;
        RECT 265.000 15.000 275.000 82.500 ;
        RECT 265.000 72.500 292.500 82.500 ;
        RECT 282.500 90.000 315.000 100.000 ;
        RECT 282.500 72.500 292.500 127.500 ;
        RECT 265.000 117.500 292.500 127.500 ;
        RECT 265.000 117.500 275.000 235.000 ;
        RECT 325.000 135.000 335.000 235.000 ;
        RECT 305.000 117.500 317.500 127.500 ;
        RECT 305.000 125.000 335.000 127.500 ;
        RECT 305.000 117.500 315.000 235.000 ;
        RECT 305.000 15.000 315.000 82.500 ;
        RECT 305.000 72.500 335.000 82.500 ;
        RECT 325.000 72.500 335.000 100.000 ;
        RECT 325.000 15.000 335.000 65.000 ;
  END 
END CLKBUF3








END LIBRARY
